VERSION 5.8 ;
BUSBITCHARS "[]" ;
DIVIDERCHAR "/" ;
UNITS
    DATABASE MICRONS 1000 ;
END UNITS

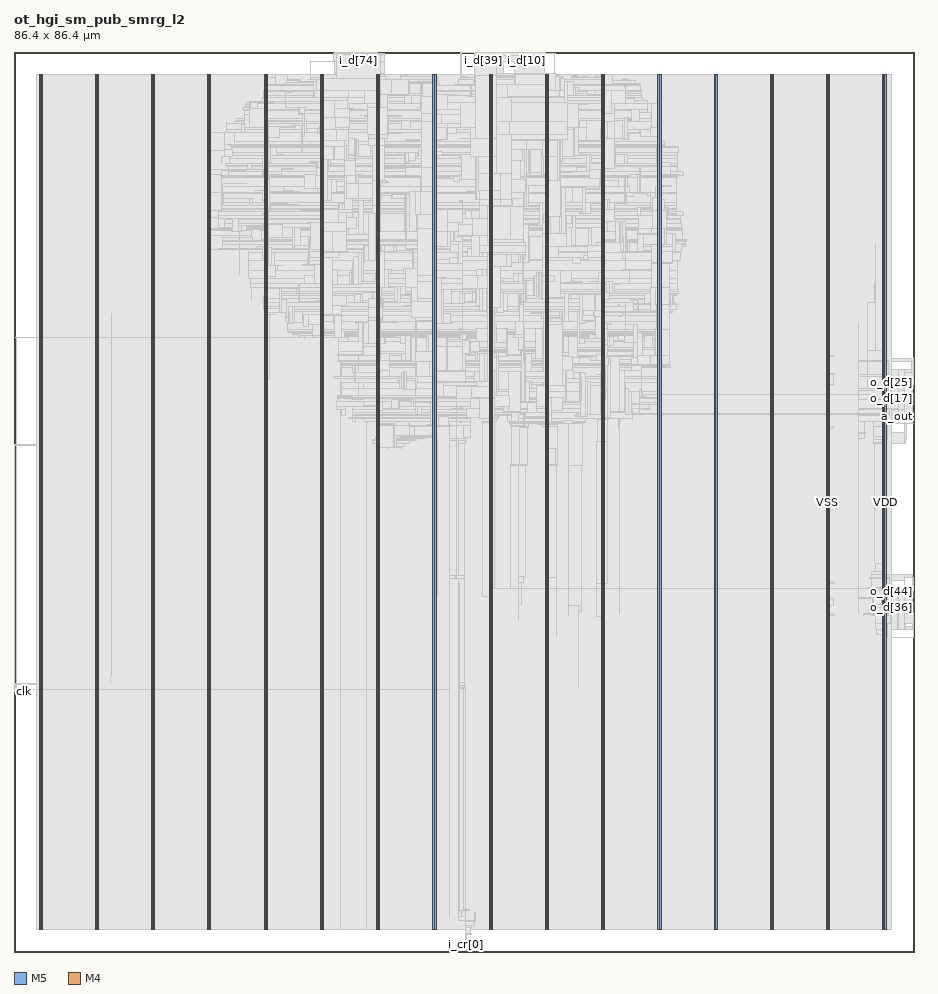
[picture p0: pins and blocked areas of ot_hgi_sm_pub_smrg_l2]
MACRO ot_hgi_sm_pub_smrg_l2
  FOREIGN ot_hgi_sm_pub_smrg_l2 0 0 ;
  CLASS BLOCK ;
  SIZE 86.4 BY 86.4 ;
  PIN a_in[0]
    DIRECTION INPUT ;
    USE SIGNAL ;
    PORT
      LAYER M5 ;
        RECT  48.048 86.316 48.072 86.4 ;
    END
  END a_in[0]
  PIN a_in[1]
    DIRECTION INPUT ;
    USE SIGNAL ;
    PORT
      LAYER M5 ;
        RECT  48.144 86.316 48.168 86.4 ;
    END
  END a_in[1]
  PIN a_out
    DIRECTION OUTPUT ;
    USE SIGNAL ;
    PORT
      LAYER M4 ;
        RECT  86.316 51.408 86.4 51.432 ;
    END
  END a_out
  PIN clk
    DIRECTION INPUT ;
    USE SIGNAL ;
    PORT
      LAYER M4 ;
        RECT  0 25.008 0.084 25.032 ;
    END
  END clk
  PIN i_cr[0]
    DIRECTION OUTPUT ;
    USE SIGNAL ;
    PORT
      LAYER M5 ;
        RECT  43.344 0 43.368 0.084 ;
    END
  END i_cr[0]
  PIN i_cr[1]
    DIRECTION OUTPUT ;
    USE SIGNAL ;
    PORT
      LAYER M5 ;
        RECT  43.44 0 43.464 0.084 ;
    END
  END i_cr[1]
  PIN i_d[0]
    DIRECTION INPUT ;
    USE SIGNAL ;
    PORT
      LAYER M5 ;
        RECT  48.24 86.316 48.264 86.4 ;
    END
  END i_d[0]
  PIN i_d[100]
    DIRECTION INPUT ;
    USE SIGNAL ;
    PORT
      LAYER M5 ;
        RECT  31.344 86.316 31.368 86.4 ;
    END
  END i_d[100]
  PIN i_d[101]
    DIRECTION INPUT ;
    USE SIGNAL ;
    PORT
      LAYER M5 ;
        RECT  31.44 86.316 31.464 86.4 ;
    END
  END i_d[101]
  PIN i_d[102]
    DIRECTION INPUT ;
    USE SIGNAL ;
    PORT
      LAYER M5 ;
        RECT  31.536 86.316 31.56 86.4 ;
    END
  END i_d[102]
  PIN i_d[103]
    DIRECTION INPUT ;
    USE SIGNAL ;
    PORT
      LAYER M5 ;
        RECT  31.632 86.316 31.656 86.4 ;
    END
  END i_d[103]
  PIN i_d[10]
    DIRECTION INPUT ;
    USE SIGNAL ;
    PORT
      LAYER M5 ;
        RECT  49.2 86.316 49.224 86.4 ;
    END
  END i_d[10]
  PIN i_d[11]
    DIRECTION INPUT ;
    USE SIGNAL ;
    PORT
      LAYER M5 ;
        RECT  49.296 86.316 49.32 86.4 ;
    END
  END i_d[11]
  PIN i_d[12]
    DIRECTION INPUT ;
    USE SIGNAL ;
    PORT
      LAYER M5 ;
        RECT  49.392 86.316 49.416 86.4 ;
    END
  END i_d[12]
  PIN i_d[13]
    DIRECTION INPUT ;
    USE SIGNAL ;
    PORT
      LAYER M5 ;
        RECT  49.488 86.316 49.512 86.4 ;
    END
  END i_d[13]
  PIN i_d[14]
    DIRECTION INPUT ;
    USE SIGNAL ;
    PORT
      LAYER M5 ;
        RECT  49.584 86.316 49.608 86.4 ;
    END
  END i_d[14]
  PIN i_d[15]
    DIRECTION INPUT ;
    USE SIGNAL ;
    PORT
      LAYER M5 ;
        RECT  49.68 86.316 49.704 86.4 ;
    END
  END i_d[15]
  PIN i_d[16]
    DIRECTION INPUT ;
    USE SIGNAL ;
    PORT
      LAYER M5 ;
        RECT  49.776 86.316 49.8 86.4 ;
    END
  END i_d[16]
  PIN i_d[17]
    DIRECTION INPUT ;
    USE SIGNAL ;
    PORT
      LAYER M5 ;
        RECT  49.872 86.316 49.896 86.4 ;
    END
  END i_d[17]
  PIN i_d[18]
    DIRECTION INPUT ;
    USE SIGNAL ;
    PORT
      LAYER M5 ;
        RECT  49.968 86.316 49.992 86.4 ;
    END
  END i_d[18]
  PIN i_d[19]
    DIRECTION INPUT ;
    USE SIGNAL ;
    PORT
      LAYER M5 ;
        RECT  50.064 86.316 50.088 86.4 ;
    END
  END i_d[19]
  PIN i_d[1]
    DIRECTION INPUT ;
    USE SIGNAL ;
    PORT
      LAYER M5 ;
        RECT  48.336 86.316 48.36 86.4 ;
    END
  END i_d[1]
  PIN i_d[20]
    DIRECTION INPUT ;
    USE SIGNAL ;
    PORT
      LAYER M5 ;
        RECT  50.16 86.316 50.184 86.4 ;
    END
  END i_d[20]
  PIN i_d[21]
    DIRECTION INPUT ;
    USE SIGNAL ;
    PORT
      LAYER M5 ;
        RECT  50.256 86.316 50.28 86.4 ;
    END
  END i_d[21]
  PIN i_d[22]
    DIRECTION INPUT ;
    USE SIGNAL ;
    PORT
      LAYER M5 ;
        RECT  50.352 86.316 50.376 86.4 ;
    END
  END i_d[22]
  PIN i_d[23]
    DIRECTION INPUT ;
    USE SIGNAL ;
    PORT
      LAYER M5 ;
        RECT  50.448 86.316 50.472 86.4 ;
    END
  END i_d[23]
  PIN i_d[24]
    DIRECTION INPUT ;
    USE SIGNAL ;
    PORT
      LAYER M5 ;
        RECT  50.544 86.316 50.568 86.4 ;
    END
  END i_d[24]
  PIN i_d[25]
    DIRECTION INPUT ;
    USE SIGNAL ;
    PORT
      LAYER M5 ;
        RECT  50.64 86.316 50.664 86.4 ;
    END
  END i_d[25]
  PIN i_d[26]
    DIRECTION INPUT ;
    USE SIGNAL ;
    PORT
      LAYER M5 ;
        RECT  50.736 86.316 50.76 86.4 ;
    END
  END i_d[26]
  PIN i_d[27]
    DIRECTION INPUT ;
    USE SIGNAL ;
    PORT
      LAYER M5 ;
        RECT  50.832 86.316 50.856 86.4 ;
    END
  END i_d[27]
  PIN i_d[28]
    DIRECTION INPUT ;
    USE SIGNAL ;
    PORT
      LAYER M5 ;
        RECT  50.928 86.316 50.952 86.4 ;
    END
  END i_d[28]
  PIN i_d[29]
    DIRECTION INPUT ;
    USE SIGNAL ;
    PORT
      LAYER M5 ;
        RECT  51.024 86.316 51.048 86.4 ;
    END
  END i_d[29]
  PIN i_d[2]
    DIRECTION INPUT ;
    USE SIGNAL ;
    PORT
      LAYER M5 ;
        RECT  48.432 86.316 48.456 86.4 ;
    END
  END i_d[2]
  PIN i_d[30]
    DIRECTION INPUT ;
    USE SIGNAL ;
    PORT
      LAYER M5 ;
        RECT  44.208 86.316 44.232 86.4 ;
    END
  END i_d[30]
  PIN i_d[31]
    DIRECTION INPUT ;
    USE SIGNAL ;
    PORT
      LAYER M5 ;
        RECT  44.304 86.316 44.328 86.4 ;
    END
  END i_d[31]
  PIN i_d[32]
    DIRECTION INPUT ;
    USE SIGNAL ;
    PORT
      LAYER M5 ;
        RECT  44.4 86.316 44.424 86.4 ;
    END
  END i_d[32]
  PIN i_d[33]
    DIRECTION INPUT ;
    USE SIGNAL ;
    PORT
      LAYER M5 ;
        RECT  44.496 86.316 44.52 86.4 ;
    END
  END i_d[33]
  PIN i_d[34]
    DIRECTION INPUT ;
    USE SIGNAL ;
    PORT
      LAYER M5 ;
        RECT  44.592 86.316 44.616 86.4 ;
    END
  END i_d[34]
  PIN i_d[35]
    DIRECTION INPUT ;
    USE SIGNAL ;
    PORT
      LAYER M5 ;
        RECT  44.688 86.316 44.712 86.4 ;
    END
  END i_d[35]
  PIN i_d[36]
    DIRECTION INPUT ;
    USE SIGNAL ;
    PORT
      LAYER M5 ;
        RECT  44.784 86.316 44.808 86.4 ;
    END
  END i_d[36]
  PIN i_d[37]
    DIRECTION INPUT ;
    USE SIGNAL ;
    PORT
      LAYER M5 ;
        RECT  44.88 86.316 44.904 86.4 ;
    END
  END i_d[37]
  PIN i_d[38]
    DIRECTION INPUT ;
    USE SIGNAL ;
    PORT
      LAYER M5 ;
        RECT  44.976 86.316 45 86.4 ;
    END
  END i_d[38]
  PIN i_d[39]
    DIRECTION INPUT ;
    USE SIGNAL ;
    PORT
      LAYER M5 ;
        RECT  45.072 86.316 45.096 86.4 ;
    END
  END i_d[39]
  PIN i_d[3]
    DIRECTION INPUT ;
    USE SIGNAL ;
    PORT
      LAYER M5 ;
        RECT  48.528 86.316 48.552 86.4 ;
    END
  END i_d[3]
  PIN i_d[40]
    DIRECTION INPUT ;
    USE SIGNAL ;
    PORT
      LAYER M5 ;
        RECT  45.168 86.316 45.192 86.4 ;
    END
  END i_d[40]
  PIN i_d[41]
    DIRECTION INPUT ;
    USE SIGNAL ;
    PORT
      LAYER M5 ;
        RECT  45.264 86.316 45.288 86.4 ;
    END
  END i_d[41]
  PIN i_d[42]
    DIRECTION INPUT ;
    USE SIGNAL ;
    PORT
      LAYER M5 ;
        RECT  45.36 86.316 45.384 86.4 ;
    END
  END i_d[42]
  PIN i_d[43]
    DIRECTION INPUT ;
    USE SIGNAL ;
    PORT
      LAYER M5 ;
        RECT  45.456 86.316 45.48 86.4 ;
    END
  END i_d[43]
  PIN i_d[44]
    DIRECTION INPUT ;
    USE SIGNAL ;
    PORT
      LAYER M5 ;
        RECT  45.552 86.316 45.576 86.4 ;
    END
  END i_d[44]
  PIN i_d[45]
    DIRECTION INPUT ;
    USE SIGNAL ;
    PORT
      LAYER M5 ;
        RECT  45.648 86.316 45.672 86.4 ;
    END
  END i_d[45]
  PIN i_d[46]
    DIRECTION INPUT ;
    USE SIGNAL ;
    PORT
      LAYER M5 ;
        RECT  45.744 86.316 45.768 86.4 ;
    END
  END i_d[46]
  PIN i_d[47]
    DIRECTION INPUT ;
    USE SIGNAL ;
    PORT
      LAYER M5 ;
        RECT  45.84 86.316 45.864 86.4 ;
    END
  END i_d[47]
  PIN i_d[48]
    DIRECTION INPUT ;
    USE SIGNAL ;
    PORT
      LAYER M5 ;
        RECT  45.936 86.316 45.96 86.4 ;
    END
  END i_d[48]
  PIN i_d[49]
    DIRECTION INPUT ;
    USE SIGNAL ;
    PORT
      LAYER M5 ;
        RECT  46.032 86.316 46.056 86.4 ;
    END
  END i_d[49]
  PIN i_d[4]
    DIRECTION INPUT ;
    USE SIGNAL ;
    PORT
      LAYER M5 ;
        RECT  48.624 86.316 48.648 86.4 ;
    END
  END i_d[4]
  PIN i_d[50]
    DIRECTION INPUT ;
    USE SIGNAL ;
    PORT
      LAYER M5 ;
        RECT  46.128 86.316 46.152 86.4 ;
    END
  END i_d[50]
  PIN i_d[51]
    DIRECTION INPUT ;
    USE SIGNAL ;
    PORT
      LAYER M5 ;
        RECT  46.224 86.316 46.248 86.4 ;
    END
  END i_d[51]
  PIN i_d[52]
    DIRECTION INPUT ;
    USE SIGNAL ;
    PORT
      LAYER M5 ;
        RECT  46.32 86.316 46.344 86.4 ;
    END
  END i_d[52]
  PIN i_d[53]
    DIRECTION INPUT ;
    USE SIGNAL ;
    PORT
      LAYER M5 ;
        RECT  46.416 86.316 46.44 86.4 ;
    END
  END i_d[53]
  PIN i_d[54]
    DIRECTION INPUT ;
    USE SIGNAL ;
    PORT
      LAYER M5 ;
        RECT  46.512 86.316 46.536 86.4 ;
    END
  END i_d[54]
  PIN i_d[55]
    DIRECTION INPUT ;
    USE SIGNAL ;
    PORT
      LAYER M5 ;
        RECT  46.608 86.316 46.632 86.4 ;
    END
  END i_d[55]
  PIN i_d[56]
    DIRECTION INPUT ;
    USE SIGNAL ;
    PORT
      LAYER M5 ;
        RECT  46.704 86.316 46.728 86.4 ;
    END
  END i_d[56]
  PIN i_d[57]
    DIRECTION INPUT ;
    USE SIGNAL ;
    PORT
      LAYER M5 ;
        RECT  46.8 86.316 46.824 86.4 ;
    END
  END i_d[57]
  PIN i_d[58]
    DIRECTION INPUT ;
    USE SIGNAL ;
    PORT
      LAYER M5 ;
        RECT  46.896 86.316 46.92 86.4 ;
    END
  END i_d[58]
  PIN i_d[59]
    DIRECTION INPUT ;
    USE SIGNAL ;
    PORT
      LAYER M5 ;
        RECT  46.992 86.316 47.016 86.4 ;
    END
  END i_d[59]
  PIN i_d[5]
    DIRECTION INPUT ;
    USE SIGNAL ;
    PORT
      LAYER M5 ;
        RECT  48.72 86.316 48.744 86.4 ;
    END
  END i_d[5]
  PIN i_d[60]
    DIRECTION INPUT ;
    USE SIGNAL ;
    PORT
      LAYER M5 ;
        RECT  47.088 86.316 47.112 86.4 ;
    END
  END i_d[60]
  PIN i_d[61]
    DIRECTION INPUT ;
    USE SIGNAL ;
    PORT
      LAYER M5 ;
        RECT  47.184 86.316 47.208 86.4 ;
    END
  END i_d[61]
  PIN i_d[62]
    DIRECTION INPUT ;
    USE SIGNAL ;
    PORT
      LAYER M5 ;
        RECT  31.92 86.316 31.944 86.4 ;
    END
  END i_d[62]
  PIN i_d[63]
    DIRECTION INPUT ;
    USE SIGNAL ;
    PORT
      LAYER M5 ;
        RECT  32.016 86.316 32.04 86.4 ;
    END
  END i_d[63]
  PIN i_d[64]
    DIRECTION INPUT ;
    USE SIGNAL ;
    PORT
      LAYER M5 ;
        RECT  32.112 86.316 32.136 86.4 ;
    END
  END i_d[64]
  PIN i_d[65]
    DIRECTION INPUT ;
    USE SIGNAL ;
    PORT
      LAYER M5 ;
        RECT  32.208 86.316 32.232 86.4 ;
    END
  END i_d[65]
  PIN i_d[66]
    DIRECTION INPUT ;
    USE SIGNAL ;
    PORT
      LAYER M5 ;
        RECT  32.304 86.316 32.328 86.4 ;
    END
  END i_d[66]
  PIN i_d[67]
    DIRECTION INPUT ;
    USE SIGNAL ;
    PORT
      LAYER M5 ;
        RECT  32.4 86.316 32.424 86.4 ;
    END
  END i_d[67]
  PIN i_d[68]
    DIRECTION INPUT ;
    USE SIGNAL ;
    PORT
      LAYER M5 ;
        RECT  32.496 86.316 32.52 86.4 ;
    END
  END i_d[68]
  PIN i_d[69]
    DIRECTION INPUT ;
    USE SIGNAL ;
    PORT
      LAYER M5 ;
        RECT  32.592 86.316 32.616 86.4 ;
    END
  END i_d[69]
  PIN i_d[6]
    DIRECTION INPUT ;
    USE SIGNAL ;
    PORT
      LAYER M5 ;
        RECT  48.816 86.316 48.84 86.4 ;
    END
  END i_d[6]
  PIN i_d[70]
    DIRECTION INPUT ;
    USE SIGNAL ;
    PORT
      LAYER M5 ;
        RECT  32.688 86.316 32.712 86.4 ;
    END
  END i_d[70]
  PIN i_d[71]
    DIRECTION INPUT ;
    USE SIGNAL ;
    PORT
      LAYER M5 ;
        RECT  32.784 86.316 32.808 86.4 ;
    END
  END i_d[71]
  PIN i_d[72]
    DIRECTION INPUT ;
    USE SIGNAL ;
    PORT
      LAYER M5 ;
        RECT  32.88 86.316 32.904 86.4 ;
    END
  END i_d[72]
  PIN i_d[73]
    DIRECTION INPUT ;
    USE SIGNAL ;
    PORT
      LAYER M5 ;
        RECT  32.976 86.316 33 86.4 ;
    END
  END i_d[73]
  PIN i_d[74]
    DIRECTION INPUT ;
    USE SIGNAL ;
    PORT
      LAYER M5 ;
        RECT  33.072 86.316 33.096 86.4 ;
    END
  END i_d[74]
  PIN i_d[75]
    DIRECTION INPUT ;
    USE SIGNAL ;
    PORT
      LAYER M5 ;
        RECT  33.168 86.316 33.192 86.4 ;
    END
  END i_d[75]
  PIN i_d[76]
    DIRECTION INPUT ;
    USE SIGNAL ;
    PORT
      LAYER M5 ;
        RECT  33.264 86.316 33.288 86.4 ;
    END
  END i_d[76]
  PIN i_d[77]
    DIRECTION INPUT ;
    USE SIGNAL ;
    PORT
      LAYER M5 ;
        RECT  33.36 86.316 33.384 86.4 ;
    END
  END i_d[77]
  PIN i_d[78]
    DIRECTION INPUT ;
    USE SIGNAL ;
    PORT
      LAYER M5 ;
        RECT  33.456 86.316 33.48 86.4 ;
    END
  END i_d[78]
  PIN i_d[79]
    DIRECTION INPUT ;
    USE SIGNAL ;
    PORT
      LAYER M5 ;
        RECT  33.552 86.316 33.576 86.4 ;
    END
  END i_d[79]
  PIN i_d[7]
    DIRECTION INPUT ;
    USE SIGNAL ;
    PORT
      LAYER M5 ;
        RECT  48.912 86.316 48.936 86.4 ;
    END
  END i_d[7]
  PIN i_d[80]
    DIRECTION INPUT ;
    USE SIGNAL ;
    PORT
      LAYER M5 ;
        RECT  33.648 86.316 33.672 86.4 ;
    END
  END i_d[80]
  PIN i_d[81]
    DIRECTION INPUT ;
    USE SIGNAL ;
    PORT
      LAYER M5 ;
        RECT  33.744 86.316 33.768 86.4 ;
    END
  END i_d[81]
  PIN i_d[82]
    DIRECTION INPUT ;
    USE SIGNAL ;
    PORT
      LAYER M5 ;
        RECT  33.84 86.316 33.864 86.4 ;
    END
  END i_d[82]
  PIN i_d[83]
    DIRECTION INPUT ;
    USE SIGNAL ;
    PORT
      LAYER M5 ;
        RECT  33.936 86.316 33.96 86.4 ;
    END
  END i_d[83]
  PIN i_d[84]
    DIRECTION INPUT ;
    USE SIGNAL ;
    PORT
      LAYER M5 ;
        RECT  34.032 86.316 34.056 86.4 ;
    END
  END i_d[84]
  PIN i_d[85]
    DIRECTION INPUT ;
    USE SIGNAL ;
    PORT
      LAYER M5 ;
        RECT  34.128 86.316 34.152 86.4 ;
    END
  END i_d[85]
  PIN i_d[86]
    DIRECTION INPUT ;
    USE SIGNAL ;
    PORT
      LAYER M5 ;
        RECT  34.224 86.316 34.248 86.4 ;
    END
  END i_d[86]
  PIN i_d[87]
    DIRECTION INPUT ;
    USE SIGNAL ;
    PORT
      LAYER M5 ;
        RECT  34.32 86.316 34.344 86.4 ;
    END
  END i_d[87]
  PIN i_d[88]
    DIRECTION INPUT ;
    USE SIGNAL ;
    PORT
      LAYER M5 ;
        RECT  34.416 86.316 34.44 86.4 ;
    END
  END i_d[88]
  PIN i_d[89]
    DIRECTION INPUT ;
    USE SIGNAL ;
    PORT
      LAYER M5 ;
        RECT  34.512 86.316 34.536 86.4 ;
    END
  END i_d[89]
  PIN i_d[8]
    DIRECTION INPUT ;
    USE SIGNAL ;
    PORT
      LAYER M5 ;
        RECT  49.008 86.316 49.032 86.4 ;
    END
  END i_d[8]
  PIN i_d[90]
    DIRECTION INPUT ;
    USE SIGNAL ;
    PORT
      LAYER M5 ;
        RECT  34.608 86.316 34.632 86.4 ;
    END
  END i_d[90]
  PIN i_d[91]
    DIRECTION INPUT ;
    USE SIGNAL ;
    PORT
      LAYER M5 ;
        RECT  34.704 86.316 34.728 86.4 ;
    END
  END i_d[91]
  PIN i_d[92]
    DIRECTION INPUT ;
    USE SIGNAL ;
    PORT
      LAYER M5 ;
        RECT  34.8 86.316 34.824 86.4 ;
    END
  END i_d[92]
  PIN i_d[93]
    DIRECTION INPUT ;
    USE SIGNAL ;
    PORT
      LAYER M5 ;
        RECT  34.896 86.316 34.92 86.4 ;
    END
  END i_d[93]
  PIN i_d[94]
    DIRECTION INPUT ;
    USE SIGNAL ;
    PORT
      LAYER M5 ;
        RECT  30.768 86.316 30.792 86.4 ;
    END
  END i_d[94]
  PIN i_d[95]
    DIRECTION INPUT ;
    USE SIGNAL ;
    PORT
      LAYER M5 ;
        RECT  30.864 86.316 30.888 86.4 ;
    END
  END i_d[95]
  PIN i_d[96]
    DIRECTION INPUT ;
    USE SIGNAL ;
    PORT
      LAYER M5 ;
        RECT  30.96 86.316 30.984 86.4 ;
    END
  END i_d[96]
  PIN i_d[97]
    DIRECTION INPUT ;
    USE SIGNAL ;
    PORT
      LAYER M5 ;
        RECT  31.056 86.316 31.08 86.4 ;
    END
  END i_d[97]
  PIN i_d[98]
    DIRECTION INPUT ;
    USE SIGNAL ;
    PORT
      LAYER M5 ;
        RECT  31.152 86.316 31.176 86.4 ;
    END
  END i_d[98]
  PIN i_d[99]
    DIRECTION INPUT ;
    USE SIGNAL ;
    PORT
      LAYER M5 ;
        RECT  31.248 86.316 31.272 86.4 ;
    END
  END i_d[99]
  PIN i_d[9]
    DIRECTION INPUT ;
    USE SIGNAL ;
    PORT
      LAYER M5 ;
        RECT  49.104 86.316 49.128 86.4 ;
    END
  END i_d[9]
  PIN i_v[0]
    DIRECTION INPUT ;
    USE SIGNAL ;
    PORT
      LAYER M5 ;
        RECT  31.728 86.316 31.752 86.4 ;
    END
  END i_v[0]
  PIN i_v[1]
    DIRECTION INPUT ;
    USE SIGNAL ;
    PORT
      LAYER M5 ;
        RECT  31.824 86.316 31.848 86.4 ;
    END
  END i_v[1]
  PIN o_cr
    DIRECTION INPUT ;
    USE SIGNAL ;
    PORT
      LAYER M4 ;
        RECT  0 25.104 0.084 25.128 ;
    END
  END o_cr
  PIN o_d[0]
    DIRECTION OUTPUT ;
    USE SIGNAL ;
    PORT
      LAYER M4 ;
        RECT  86.316 51.504 86.4 51.528 ;
    END
  END o_d[0]
  PIN o_d[10]
    DIRECTION OUTPUT ;
    USE SIGNAL ;
    PORT
      LAYER M4 ;
        RECT  86.316 52.464 86.4 52.488 ;
    END
  END o_d[10]
  PIN o_d[11]
    DIRECTION OUTPUT ;
    USE SIGNAL ;
    PORT
      LAYER M4 ;
        RECT  86.316 52.56 86.4 52.584 ;
    END
  END o_d[11]
  PIN o_d[12]
    DIRECTION OUTPUT ;
    USE SIGNAL ;
    PORT
      LAYER M4 ;
        RECT  86.316 52.656 86.4 52.68 ;
    END
  END o_d[12]
  PIN o_d[13]
    DIRECTION OUTPUT ;
    USE SIGNAL ;
    PORT
      LAYER M4 ;
        RECT  86.316 52.752 86.4 52.776 ;
    END
  END o_d[13]
  PIN o_d[14]
    DIRECTION OUTPUT ;
    USE SIGNAL ;
    PORT
      LAYER M4 ;
        RECT  86.316 52.848 86.4 52.872 ;
    END
  END o_d[14]
  PIN o_d[15]
    DIRECTION OUTPUT ;
    USE SIGNAL ;
    PORT
      LAYER M4 ;
        RECT  86.316 52.944 86.4 52.968 ;
    END
  END o_d[15]
  PIN o_d[16]
    DIRECTION OUTPUT ;
    USE SIGNAL ;
    PORT
      LAYER M4 ;
        RECT  86.316 53.04 86.4 53.064 ;
    END
  END o_d[16]
  PIN o_d[17]
    DIRECTION OUTPUT ;
    USE SIGNAL ;
    PORT
      LAYER M4 ;
        RECT  86.316 53.136 86.4 53.16 ;
    END
  END o_d[17]
  PIN o_d[18]
    DIRECTION OUTPUT ;
    USE SIGNAL ;
    PORT
      LAYER M4 ;
        RECT  86.316 53.232 86.4 53.256 ;
    END
  END o_d[18]
  PIN o_d[19]
    DIRECTION OUTPUT ;
    USE SIGNAL ;
    PORT
      LAYER M4 ;
        RECT  86.316 53.328 86.4 53.352 ;
    END
  END o_d[19]
  PIN o_d[1]
    DIRECTION OUTPUT ;
    USE SIGNAL ;
    PORT
      LAYER M4 ;
        RECT  86.316 51.6 86.4 51.624 ;
    END
  END o_d[1]
  PIN o_d[20]
    DIRECTION OUTPUT ;
    USE SIGNAL ;
    PORT
      LAYER M4 ;
        RECT  86.316 53.424 86.4 53.448 ;
    END
  END o_d[20]
  PIN o_d[21]
    DIRECTION OUTPUT ;
    USE SIGNAL ;
    PORT
      LAYER M4 ;
        RECT  86.316 53.52 86.4 53.544 ;
    END
  END o_d[21]
  PIN o_d[22]
    DIRECTION OUTPUT ;
    USE SIGNAL ;
    PORT
      LAYER M4 ;
        RECT  86.316 53.616 86.4 53.64 ;
    END
  END o_d[22]
  PIN o_d[23]
    DIRECTION OUTPUT ;
    USE SIGNAL ;
    PORT
      LAYER M4 ;
        RECT  86.316 53.712 86.4 53.736 ;
    END
  END o_d[23]
  PIN o_d[24]
    DIRECTION OUTPUT ;
    USE SIGNAL ;
    PORT
      LAYER M4 ;
        RECT  86.316 53.808 86.4 53.832 ;
    END
  END o_d[24]
  PIN o_d[25]
    DIRECTION OUTPUT ;
    USE SIGNAL ;
    PORT
      LAYER M4 ;
        RECT  86.316 53.904 86.4 53.928 ;
    END
  END o_d[25]
  PIN o_d[26]
    DIRECTION OUTPUT ;
    USE SIGNAL ;
    PORT
      LAYER M4 ;
        RECT  86.316 54 86.4 54.024 ;
    END
  END o_d[26]
  PIN o_d[27]
    DIRECTION OUTPUT ;
    USE SIGNAL ;
    PORT
      LAYER M4 ;
        RECT  86.316 54.096 86.4 54.12 ;
    END
  END o_d[27]
  PIN o_d[28]
    DIRECTION OUTPUT ;
    USE SIGNAL ;
    PORT
      LAYER M4 ;
        RECT  86.316 54.192 86.4 54.216 ;
    END
  END o_d[28]
  PIN o_d[29]
    DIRECTION OUTPUT ;
    USE SIGNAL ;
    PORT
      LAYER M4 ;
        RECT  86.316 54.288 86.4 54.312 ;
    END
  END o_d[29]
  PIN o_d[2]
    DIRECTION OUTPUT ;
    USE SIGNAL ;
    PORT
      LAYER M4 ;
        RECT  86.316 51.696 86.4 51.72 ;
    END
  END o_d[2]
  PIN o_d[30]
    DIRECTION OUTPUT ;
    USE SIGNAL ;
    PORT
      LAYER M4 ;
        RECT  86.316 54.384 86.4 54.408 ;
    END
  END o_d[30]
  PIN o_d[31]
    DIRECTION OUTPUT ;
    USE SIGNAL ;
    PORT
      LAYER M4 ;
        RECT  86.316 32.592 86.4 32.616 ;
    END
  END o_d[31]
  PIN o_d[32]
    DIRECTION OUTPUT ;
    USE SIGNAL ;
    PORT
      LAYER M4 ;
        RECT  86.316 32.688 86.4 32.712 ;
    END
  END o_d[32]
  PIN o_d[33]
    DIRECTION OUTPUT ;
    USE SIGNAL ;
    PORT
      LAYER M4 ;
        RECT  86.316 32.784 86.4 32.808 ;
    END
  END o_d[33]
  PIN o_d[34]
    DIRECTION OUTPUT ;
    USE SIGNAL ;
    PORT
      LAYER M4 ;
        RECT  86.316 32.88 86.4 32.904 ;
    END
  END o_d[34]
  PIN o_d[35]
    DIRECTION OUTPUT ;
    USE SIGNAL ;
    PORT
      LAYER M4 ;
        RECT  86.316 32.976 86.4 33 ;
    END
  END o_d[35]
  PIN o_d[36]
    DIRECTION OUTPUT ;
    USE SIGNAL ;
    PORT
      LAYER M4 ;
        RECT  86.316 33.072 86.4 33.096 ;
    END
  END o_d[36]
  PIN o_d[37]
    DIRECTION OUTPUT ;
    USE SIGNAL ;
    PORT
      LAYER M4 ;
        RECT  86.316 33.168 86.4 33.192 ;
    END
  END o_d[37]
  PIN o_d[38]
    DIRECTION OUTPUT ;
    USE SIGNAL ;
    PORT
      LAYER M4 ;
        RECT  86.316 33.264 86.4 33.288 ;
    END
  END o_d[38]
  PIN o_d[39]
    DIRECTION OUTPUT ;
    USE SIGNAL ;
    PORT
      LAYER M4 ;
        RECT  86.316 33.36 86.4 33.384 ;
    END
  END o_d[39]
  PIN o_d[3]
    DIRECTION OUTPUT ;
    USE SIGNAL ;
    PORT
      LAYER M4 ;
        RECT  86.316 51.792 86.4 51.816 ;
    END
  END o_d[3]
  PIN o_d[40]
    DIRECTION OUTPUT ;
    USE SIGNAL ;
    PORT
      LAYER M4 ;
        RECT  86.316 33.456 86.4 33.48 ;
    END
  END o_d[40]
  PIN o_d[41]
    DIRECTION OUTPUT ;
    USE SIGNAL ;
    PORT
      LAYER M4 ;
        RECT  86.316 33.552 86.4 33.576 ;
    END
  END o_d[41]
  PIN o_d[42]
    DIRECTION OUTPUT ;
    USE SIGNAL ;
    PORT
      LAYER M4 ;
        RECT  86.316 33.648 86.4 33.672 ;
    END
  END o_d[42]
  PIN o_d[43]
    DIRECTION OUTPUT ;
    USE SIGNAL ;
    PORT
      LAYER M4 ;
        RECT  86.316 33.744 86.4 33.768 ;
    END
  END o_d[43]
  PIN o_d[44]
    DIRECTION OUTPUT ;
    USE SIGNAL ;
    PORT
      LAYER M4 ;
        RECT  86.316 33.84 86.4 33.864 ;
    END
  END o_d[44]
  PIN o_d[45]
    DIRECTION OUTPUT ;
    USE SIGNAL ;
    PORT
      LAYER M4 ;
        RECT  86.316 33.936 86.4 33.96 ;
    END
  END o_d[45]
  PIN o_d[46]
    DIRECTION OUTPUT ;
    USE SIGNAL ;
    PORT
      LAYER M4 ;
        RECT  86.316 34.032 86.4 34.056 ;
    END
  END o_d[46]
  PIN o_d[47]
    DIRECTION OUTPUT ;
    USE SIGNAL ;
    PORT
      LAYER M4 ;
        RECT  86.316 34.128 86.4 34.152 ;
    END
  END o_d[47]
  PIN o_d[48]
    DIRECTION OUTPUT ;
    USE SIGNAL ;
    PORT
      LAYER M4 ;
        RECT  86.316 34.224 86.4 34.248 ;
    END
  END o_d[48]
  PIN o_d[49]
    DIRECTION OUTPUT ;
    USE SIGNAL ;
    PORT
      LAYER M4 ;
        RECT  86.316 34.32 86.4 34.344 ;
    END
  END o_d[49]
  PIN o_d[4]
    DIRECTION OUTPUT ;
    USE SIGNAL ;
    PORT
      LAYER M4 ;
        RECT  86.316 51.888 86.4 51.912 ;
    END
  END o_d[4]
  PIN o_d[50]
    DIRECTION OUTPUT ;
    USE SIGNAL ;
    PORT
      LAYER M4 ;
        RECT  86.316 34.416 86.4 34.44 ;
    END
  END o_d[50]
  PIN o_d[51]
    DIRECTION OUTPUT ;
    USE SIGNAL ;
    PORT
      LAYER M4 ;
        RECT  86.316 34.512 86.4 34.536 ;
    END
  END o_d[51]
  PIN o_d[5]
    DIRECTION OUTPUT ;
    USE SIGNAL ;
    PORT
      LAYER M4 ;
        RECT  86.316 51.984 86.4 52.008 ;
    END
  END o_d[5]
  PIN o_d[6]
    DIRECTION OUTPUT ;
    USE SIGNAL ;
    PORT
      LAYER M4 ;
        RECT  86.316 52.08 86.4 52.104 ;
    END
  END o_d[6]
  PIN o_d[7]
    DIRECTION OUTPUT ;
    USE SIGNAL ;
    PORT
      LAYER M4 ;
        RECT  86.316 52.176 86.4 52.2 ;
    END
  END o_d[7]
  PIN o_d[8]
    DIRECTION OUTPUT ;
    USE SIGNAL ;
    PORT
      LAYER M4 ;
        RECT  86.316 52.272 86.4 52.296 ;
    END
  END o_d[8]
  PIN o_d[9]
    DIRECTION OUTPUT ;
    USE SIGNAL ;
    PORT
      LAYER M4 ;
        RECT  86.316 52.368 86.4 52.392 ;
    END
  END o_d[9]
  PIN o_v
    DIRECTION OUTPUT ;
    USE SIGNAL ;
    PORT
      LAYER M4 ;
        RECT  86.316 34.608 86.4 34.632 ;
    END
  END o_v
  PIN rn
    DIRECTION INPUT ;
    USE SIGNAL ;
    PORT
      LAYER M4 ;
        RECT  0 25.2 0.084 25.224 ;
    END
  END rn
  PIN xb
    DIRECTION INPUT ;
    USE SIGNAL ;
    PORT
      LAYER M4 ;
        RECT  0 25.296 0.084 25.32 ;
    END
  END xb
  PIN VDD
    DIRECTION INOUT ;
    USE POWER ;
    PORT
      LAYER M5 ;
        RECT  83.592 2.151 83.712 84.249 ;
        RECT  78.192 2.151 78.312 84.249 ;
        RECT  72.792 2.151 72.912 84.249 ;
        RECT  67.392 2.151 67.512 84.249 ;
        RECT  61.992 2.151 62.112 84.249 ;
        RECT  56.592 2.151 56.712 84.249 ;
        RECT  51.192 2.151 51.312 84.249 ;
        RECT  45.792 2.151 45.912 84.249 ;
        RECT  40.392 2.151 40.512 84.249 ;
        RECT  34.992 2.151 35.112 84.249 ;
        RECT  29.592 2.151 29.712 84.249 ;
        RECT  24.192 2.151 24.312 84.249 ;
        RECT  18.792 2.151 18.912 84.249 ;
        RECT  13.392 2.151 13.512 84.249 ;
        RECT  7.992 2.151 8.112 84.249 ;
        RECT  2.592 2.151 2.712 84.249 ;
    END
  END VDD
  PIN VSS
    DIRECTION INOUT ;
    USE GROUND ;
    PORT
      LAYER M5 ;
        RECT  83.4 2.137 83.52 84.263 ;
        RECT  78 2.137 78.12 84.263 ;
        RECT  72.6 2.137 72.72 84.263 ;
        RECT  67.2 2.137 67.32 84.263 ;
        RECT  61.8 2.137 61.92 84.263 ;
        RECT  56.4 2.137 56.52 84.263 ;
        RECT  51 2.137 51.12 84.263 ;
        RECT  45.6 2.137 45.72 84.263 ;
        RECT  40.2 2.137 40.32 84.263 ;
        RECT  34.8 2.137 34.92 84.263 ;
        RECT  29.4 2.137 29.52 84.263 ;
        RECT  24 2.137 24.12 84.263 ;
        RECT  18.6 2.137 18.72 84.263 ;
        RECT  13.2 2.137 13.32 84.263 ;
        RECT  7.8 2.137 7.92 84.263 ;
        RECT  2.4 2.137 2.52 84.263 ;
    END
  END VSS
  # OT_OBS_CLOSED layer=M5 d_um=1.536 added=113
  OBS
    LAYER RVTN ;
     RECT  2.16 2.16 84.24 2.295 ;
     RECT  2.16 2.565 84.24 2.835 ;
     RECT  2.16 3.105 84.24 3.375 ;
     RECT  2.16 3.645 84.24 3.915 ;
     RECT  2.16 4.185 84.24 4.455 ;
     RECT  2.16 4.725 84.24 4.995 ;
     RECT  2.16 5.265 84.24 5.535 ;
     RECT  2.16 5.805 84.24 6.075 ;
     RECT  2.16 6.345 84.24 6.615 ;
     RECT  2.16 6.885 84.24 7.155 ;
     RECT  2.16 7.425 84.24 7.695 ;
     RECT  2.16 7.965 84.24 8.235 ;
     RECT  2.16 8.505 84.24 8.775 ;
     RECT  2.16 9.045 84.24 9.315 ;
     RECT  2.16 9.585 84.24 9.855 ;
     RECT  2.16 10.125 84.24 10.395 ;
     RECT  2.16 10.665 84.24 10.935 ;
     RECT  2.16 11.205 84.24 11.475 ;
     RECT  2.16 11.745 84.24 12.015 ;
     RECT  2.16 12.285 84.24 12.555 ;
     RECT  2.16 12.825 84.24 13.095 ;
     RECT  2.16 13.365 84.24 13.635 ;
     RECT  2.16 13.905 84.24 14.175 ;
     RECT  2.16 14.445 84.24 14.715 ;
     RECT  2.16 14.985 84.24 15.255 ;
     RECT  2.16 15.525 84.24 15.795 ;
     RECT  2.16 16.065 84.24 16.335 ;
     RECT  2.16 16.605 84.24 16.875 ;
     RECT  2.16 17.145 84.24 17.415 ;
     RECT  2.16 17.685 84.24 17.955 ;
     RECT  2.16 18.225 84.24 18.495 ;
     RECT  2.16 18.765 84.24 19.035 ;
     RECT  2.16 19.305 84.24 19.575 ;
     RECT  2.16 19.845 84.24 20.115 ;
     RECT  2.16 20.385 84.24 20.655 ;
     RECT  2.16 20.925 84.24 21.195 ;
     RECT  2.16 21.465 84.24 21.735 ;
     RECT  2.16 22.005 84.24 22.275 ;
     RECT  2.16 22.545 84.24 22.815 ;
     RECT  2.16 23.085 84.24 23.355 ;
     RECT  2.16 23.625 84.24 23.895 ;
     RECT  2.16 24.165 84.24 24.435 ;
     RECT  2.16 24.705 84.24 24.975 ;
     RECT  2.16 25.245 84.24 25.515 ;
     RECT  2.16 25.785 84.24 26.055 ;
     RECT  2.16 26.325 84.24 26.595 ;
     RECT  2.16 26.865 84.24 27.135 ;
     RECT  2.16 27.405 84.24 27.675 ;
     RECT  2.16 27.945 84.24 28.215 ;
     RECT  2.16 28.485 84.24 28.755 ;
     RECT  2.16 29.025 84.24 29.295 ;
     RECT  2.16 29.565 84.24 29.835 ;
     RECT  2.16 30.105 84.24 30.375 ;
     RECT  2.16 30.645 84.24 30.915 ;
     RECT  2.16 31.185 84.24 31.455 ;
     RECT  2.16 31.725 84.24 31.995 ;
     RECT  2.16 32.265 84.24 32.535 ;
     RECT  2.16 32.805 84.24 33.075 ;
     RECT  2.16 33.345 84.24 33.615 ;
     RECT  2.16 33.885 84.24 34.155 ;
     RECT  2.16 34.425 84.24 34.695 ;
     RECT  2.16 34.965 84.24 35.235 ;
     RECT  2.16 35.505 84.24 35.775 ;
     RECT  2.16 36.045 84.24 36.315 ;
     RECT  2.16 36.585 84.24 36.855 ;
     RECT  2.16 37.125 84.24 37.395 ;
     RECT  2.16 37.665 84.24 37.935 ;
     RECT  2.16 38.205 84.24 38.475 ;
     RECT  2.16 38.745 84.24 39.015 ;
     RECT  2.16 39.285 84.24 39.555 ;
     RECT  2.16 39.825 84.24 40.095 ;
     RECT  2.16 40.365 84.24 40.635 ;
     RECT  2.16 40.905 84.24 41.175 ;
     RECT  2.16 41.445 84.24 41.715 ;
     RECT  2.16 41.985 84.24 42.255 ;
     RECT  2.16 42.525 84.24 42.795 ;
     RECT  2.16 43.065 84.24 43.335 ;
     RECT  2.16 43.605 84.24 43.875 ;
     RECT  2.16 44.145 84.24 44.415 ;
     RECT  2.16 44.685 84.24 44.955 ;
     RECT  2.16 45.225 84.24 45.495 ;
     RECT  2.16 45.765 84.24 46.035 ;
     RECT  2.16 46.305 84.24 46.575 ;
     RECT  2.16 46.845 84.24 47.115 ;
     RECT  2.16 47.385 84.24 47.655 ;
     RECT  2.16 47.925 84.24 48.195 ;
     RECT  2.16 48.465 84.24 48.735 ;
     RECT  2.16 49.005 84.24 49.275 ;
     RECT  2.16 49.545 84.24 49.815 ;
     RECT  2.16 50.085 84.24 50.355 ;
     RECT  2.16 50.625 84.24 50.895 ;
     RECT  2.16 51.165 84.24 51.435 ;
     RECT  2.16 51.705 84.24 51.975 ;
     RECT  2.16 52.245 84.24 52.515 ;
     RECT  2.16 52.785 84.24 53.055 ;
     RECT  2.16 53.325 84.24 53.595 ;
     RECT  2.16 53.865 84.24 54.135 ;
     RECT  2.16 54.405 84.24 54.675 ;
     RECT  2.16 54.945 84.24 55.215 ;
     RECT  2.16 55.485 84.24 55.755 ;
     RECT  2.16 56.025 84.24 56.295 ;
     RECT  2.16 56.565 84.24 56.835 ;
     RECT  2.16 57.105 84.24 57.375 ;
     RECT  2.16 57.645 84.24 57.915 ;
     RECT  2.16 58.185 84.24 58.455 ;
     RECT  2.16 58.725 84.24 58.995 ;
     RECT  2.16 59.265 84.24 59.535 ;
     RECT  2.16 59.805 84.24 60.075 ;
     RECT  2.16 60.345 84.24 60.615 ;
     RECT  2.16 60.885 84.24 61.155 ;
     RECT  2.16 61.425 84.24 61.695 ;
     RECT  2.16 61.965 84.24 62.235 ;
     RECT  2.16 62.505 84.24 62.775 ;
     RECT  2.16 63.045 84.24 63.315 ;
     RECT  2.16 63.585 84.24 63.855 ;
     RECT  2.16 64.125 84.24 64.395 ;
     RECT  2.16 64.665 84.24 64.935 ;
     RECT  2.16 65.205 84.24 65.475 ;
     RECT  2.16 65.745 84.24 66.015 ;
     RECT  2.16 66.285 84.24 66.555 ;
     RECT  2.16 66.825 84.24 67.095 ;
     RECT  2.16 67.365 84.24 67.635 ;
     RECT  2.16 67.905 84.24 68.175 ;
     RECT  2.16 68.445 84.24 68.715 ;
     RECT  2.16 68.985 84.24 69.255 ;
     RECT  2.16 69.525 84.24 69.795 ;
     RECT  2.16 70.065 84.24 70.335 ;
     RECT  2.16 70.605 84.24 70.875 ;
     RECT  2.16 71.145 84.24 71.415 ;
     RECT  2.16 71.685 84.24 71.955 ;
     RECT  2.16 72.225 84.24 72.495 ;
     RECT  2.16 72.765 84.24 73.035 ;
     RECT  2.16 73.305 84.24 73.575 ;
     RECT  2.16 73.845 84.24 74.115 ;
     RECT  2.16 74.385 84.24 74.655 ;
     RECT  2.16 74.925 84.24 75.195 ;
     RECT  2.16 75.465 84.24 75.735 ;
     RECT  2.16 76.005 84.24 76.275 ;
     RECT  2.16 76.545 84.24 76.815 ;
     RECT  2.16 77.085 84.24 77.355 ;
     RECT  2.16 77.625 84.24 77.895 ;
     RECT  2.16 78.165 84.24 78.435 ;
     RECT  2.16 78.705 84.24 78.975 ;
     RECT  2.16 79.245 84.24 79.515 ;
     RECT  2.16 79.785 84.24 80.055 ;
     RECT  2.16 80.325 84.24 80.595 ;
     RECT  2.16 80.865 84.24 81.135 ;
     RECT  2.16 81.405 84.24 81.675 ;
     RECT  2.16 81.945 84.24 82.215 ;
     RECT  2.16 82.485 84.24 82.755 ;
     RECT  2.16 83.025 84.24 83.295 ;
     RECT  2.16 83.565 84.24 83.835 ;
     RECT  2.16 84.105 84.24 84.24 ;
    LAYER RVTP ;
     RECT  2.16 2.295 84.24 2.565 ;
     RECT  2.16 2.835 84.24 3.105 ;
     RECT  2.16 3.375 84.24 3.645 ;
     RECT  2.16 3.915 84.24 4.185 ;
     RECT  2.16 4.455 84.24 4.725 ;
     RECT  2.16 4.995 84.24 5.265 ;
     RECT  2.16 5.535 84.24 5.805 ;
     RECT  2.16 6.075 84.24 6.345 ;
     RECT  2.16 6.615 84.24 6.885 ;
     RECT  2.16 7.155 84.24 7.425 ;
     RECT  2.16 7.695 84.24 7.965 ;
     RECT  2.16 8.235 84.24 8.505 ;
     RECT  2.16 8.775 84.24 9.045 ;
     RECT  2.16 9.315 84.24 9.585 ;
     RECT  2.16 9.855 84.24 10.125 ;
     RECT  2.16 10.395 84.24 10.665 ;
     RECT  2.16 10.935 84.24 11.205 ;
     RECT  2.16 11.475 84.24 11.745 ;
     RECT  2.16 12.015 84.24 12.285 ;
     RECT  2.16 12.555 84.24 12.825 ;
     RECT  2.16 13.095 84.24 13.365 ;
     RECT  2.16 13.635 84.24 13.905 ;
     RECT  2.16 14.175 84.24 14.445 ;
     RECT  2.16 14.715 84.24 14.985 ;
     RECT  2.16 15.255 84.24 15.525 ;
     RECT  2.16 15.795 84.24 16.065 ;
     RECT  2.16 16.335 84.24 16.605 ;
     RECT  2.16 16.875 84.24 17.145 ;
     RECT  2.16 17.415 84.24 17.685 ;
     RECT  2.16 17.955 84.24 18.225 ;
     RECT  2.16 18.495 84.24 18.765 ;
     RECT  2.16 19.035 84.24 19.305 ;
     RECT  2.16 19.575 84.24 19.845 ;
     RECT  2.16 20.115 84.24 20.385 ;
     RECT  2.16 20.655 84.24 20.925 ;
     RECT  2.16 21.195 84.24 21.465 ;
     RECT  2.16 21.735 84.24 22.005 ;
     RECT  2.16 22.275 84.24 22.545 ;
     RECT  2.16 22.815 84.24 23.085 ;
     RECT  2.16 23.355 84.24 23.625 ;
     RECT  2.16 23.895 84.24 24.165 ;
     RECT  2.16 24.435 84.24 24.705 ;
     RECT  2.16 24.975 84.24 25.245 ;
     RECT  2.16 25.515 84.24 25.785 ;
     RECT  2.16 26.055 84.24 26.325 ;
     RECT  2.16 26.595 84.24 26.865 ;
     RECT  2.16 27.135 84.24 27.405 ;
     RECT  2.16 27.675 84.24 27.945 ;
     RECT  2.16 28.215 84.24 28.485 ;
     RECT  2.16 28.755 84.24 29.025 ;
     RECT  2.16 29.295 84.24 29.565 ;
     RECT  2.16 29.835 84.24 30.105 ;
     RECT  2.16 30.375 84.24 30.645 ;
     RECT  2.16 30.915 84.24 31.185 ;
     RECT  2.16 31.455 84.24 31.725 ;
     RECT  2.16 31.995 84.24 32.265 ;
     RECT  2.16 32.535 84.24 32.805 ;
     RECT  2.16 33.075 84.24 33.345 ;
     RECT  2.16 33.615 84.24 33.885 ;
     RECT  2.16 34.155 84.24 34.425 ;
     RECT  2.16 34.695 84.24 34.965 ;
     RECT  2.16 35.235 84.24 35.505 ;
     RECT  2.16 35.775 84.24 36.045 ;
     RECT  2.16 36.315 84.24 36.585 ;
     RECT  2.16 36.855 84.24 37.125 ;
     RECT  2.16 37.395 84.24 37.665 ;
     RECT  2.16 37.935 84.24 38.205 ;
     RECT  2.16 38.475 84.24 38.745 ;
     RECT  2.16 39.015 84.24 39.285 ;
     RECT  2.16 39.555 84.24 39.825 ;
     RECT  2.16 40.095 84.24 40.365 ;
     RECT  2.16 40.635 84.24 40.905 ;
     RECT  2.16 41.175 84.24 41.445 ;
     RECT  2.16 41.715 84.24 41.985 ;
     RECT  2.16 42.255 84.24 42.525 ;
     RECT  2.16 42.795 84.24 43.065 ;
     RECT  2.16 43.335 84.24 43.605 ;
     RECT  2.16 43.875 84.24 44.145 ;
     RECT  2.16 44.415 84.24 44.685 ;
     RECT  2.16 44.955 84.24 45.225 ;
     RECT  2.16 45.495 84.24 45.765 ;
     RECT  2.16 46.035 84.24 46.305 ;
     RECT  2.16 46.575 84.24 46.845 ;
     RECT  2.16 47.115 84.24 47.385 ;
     RECT  2.16 47.655 84.24 47.925 ;
     RECT  2.16 48.195 84.24 48.465 ;
     RECT  2.16 48.735 84.24 49.005 ;
     RECT  2.16 49.275 84.24 49.545 ;
     RECT  2.16 49.815 84.24 50.085 ;
     RECT  2.16 50.355 84.24 50.625 ;
     RECT  2.16 50.895 84.24 51.165 ;
     RECT  2.16 51.435 84.24 51.705 ;
     RECT  2.16 51.975 84.24 52.245 ;
     RECT  2.16 52.515 84.24 52.785 ;
     RECT  2.16 53.055 84.24 53.325 ;
     RECT  2.16 53.595 84.24 53.865 ;
     RECT  2.16 54.135 84.24 54.405 ;
     RECT  2.16 54.675 84.24 54.945 ;
     RECT  2.16 55.215 84.24 55.485 ;
     RECT  2.16 55.755 84.24 56.025 ;
     RECT  2.16 56.295 84.24 56.565 ;
     RECT  2.16 56.835 84.24 57.105 ;
     RECT  2.16 57.375 84.24 57.645 ;
     RECT  2.16 57.915 84.24 58.185 ;
     RECT  2.16 58.455 84.24 58.725 ;
     RECT  2.16 58.995 84.24 59.265 ;
     RECT  2.16 59.535 84.24 59.805 ;
     RECT  2.16 60.075 84.24 60.345 ;
     RECT  2.16 60.615 84.24 60.885 ;
     RECT  2.16 61.155 84.24 61.425 ;
     RECT  2.16 61.695 84.24 61.965 ;
     RECT  2.16 62.235 84.24 62.505 ;
     RECT  2.16 62.775 84.24 63.045 ;
     RECT  2.16 63.315 84.24 63.585 ;
     RECT  2.16 63.855 84.24 64.125 ;
     RECT  2.16 64.395 84.24 64.665 ;
     RECT  2.16 64.935 84.24 65.205 ;
     RECT  2.16 65.475 84.24 65.745 ;
     RECT  2.16 66.015 84.24 66.285 ;
     RECT  2.16 66.555 84.24 66.825 ;
     RECT  2.16 67.095 84.24 67.365 ;
     RECT  2.16 67.635 84.24 67.905 ;
     RECT  2.16 68.175 84.24 68.445 ;
     RECT  2.16 68.715 84.24 68.985 ;
     RECT  2.16 69.255 84.24 69.525 ;
     RECT  2.16 69.795 84.24 70.065 ;
     RECT  2.16 70.335 84.24 70.605 ;
     RECT  2.16 70.875 84.24 71.145 ;
     RECT  2.16 71.415 84.24 71.685 ;
     RECT  2.16 71.955 84.24 72.225 ;
     RECT  2.16 72.495 84.24 72.765 ;
     RECT  2.16 73.035 84.24 73.305 ;
     RECT  2.16 73.575 84.24 73.845 ;
     RECT  2.16 74.115 84.24 74.385 ;
     RECT  2.16 74.655 84.24 74.925 ;
     RECT  2.16 75.195 84.24 75.465 ;
     RECT  2.16 75.735 84.24 76.005 ;
     RECT  2.16 76.275 84.24 76.545 ;
     RECT  2.16 76.815 84.24 77.085 ;
     RECT  2.16 77.355 84.24 77.625 ;
     RECT  2.16 77.895 84.24 78.165 ;
     RECT  2.16 78.435 84.24 78.705 ;
     RECT  2.16 78.975 84.24 79.245 ;
     RECT  2.16 79.515 84.24 79.785 ;
     RECT  2.16 80.055 84.24 80.325 ;
     RECT  2.16 80.595 84.24 80.865 ;
     RECT  2.16 81.135 84.24 81.405 ;
     RECT  2.16 81.675 84.24 81.945 ;
     RECT  2.16 82.215 84.24 82.485 ;
     RECT  2.16 82.755 84.24 83.025 ;
     RECT  2.16 83.295 84.24 83.565 ;
     RECT  2.16 83.835 84.24 84.105 ;
    LAYER M1 ;
     RECT  2.16 2.151 84.24 84.249 ;
    LAYER M2 ;
     RECT  0.139 25.722 2.16 25.74 ;
     RECT  0.031 48.672 2.16 48.69 ;
     RECT  2.16 2.151 31.351 84.249 ;
     RECT  31.351 2.151 33.863 84.294 ;
     RECT  33.863 2.151 84.24 84.249 ;
     RECT  84.24 30.996 84.839 34.524 ;
     RECT  84.839 30.996 84.911 34.452 ;
     RECT  84.24 50.706 84.947 55.944 ;
     RECT  84.947 51.786 85.451 55.944 ;
     RECT  84.911 30.996 85.487 34.344 ;
     RECT  84.24 35.676 85.487 36.234 ;
     RECT  85.451 51.786 85.487 53.964 ;
     RECT  85.487 53.946 85.523 53.964 ;
     RECT  85.487 30.996 85.559 33.3 ;
     RECT  84.24 48.816 85.559 49.914 ;
     RECT  85.559 49.176 85.631 49.914 ;
     RECT  85.631 49.176 85.667 49.194 ;
     RECT  84.24 56.736 86.171 57.024 ;
     RECT  85.559 32.346 86.207 33.3 ;
     RECT  85.451 54.846 86.207 55.944 ;
     RECT  85.559 30.996 86.243 31.284 ;
     RECT  85.487 35.946 86.243 36.234 ;
     RECT  85.487 51.786 86.243 52.344 ;
     RECT  86.207 54.846 86.243 55.854 ;
     RECT  84.947 50.706 86.251 50.724 ;
     RECT  86.207 33.048 86.279 33.3 ;
     RECT  86.243 54.846 86.279 54.864 ;
     RECT  86.243 31.266 86.315 31.284 ;
     RECT  86.279 33.048 86.315 33.066 ;
     RECT  86.243 52.326 86.315 52.344 ;
     RECT  86.243 55.836 86.315 55.854 ;
     RECT  86.251 50.706 86.351 50.769 ;
     RECT  84.24 30.186 86.387 30.204 ;
     RECT  86.243 35.946 86.387 35.964 ;
     RECT  86.171 57.006 86.387 57.024 ;
    LAYER M3 ;
     RECT  43.308 0.091 43.326 1.723 ;
     RECT  43.308 1.723 43.866 2.371 ;
     RECT  2.415 2.143 2.505 2.413 ;
     RECT  7.815 2.143 7.905 2.413 ;
     RECT  13.215 2.143 13.305 2.413 ;
     RECT  18.615 2.143 18.705 2.413 ;
     RECT  24.015 2.143 24.105 2.413 ;
     RECT  29.415 2.143 29.505 2.413 ;
     RECT  34.815 2.143 34.905 2.413 ;
     RECT  40.215 2.143 40.305 2.413 ;
     RECT  45.615 2.143 45.705 2.413 ;
     RECT  51.015 2.143 51.105 2.413 ;
     RECT  56.415 2.143 56.505 2.413 ;
     RECT  61.815 2.143 61.905 2.413 ;
     RECT  67.215 2.143 67.305 2.413 ;
     RECT  72.615 2.143 72.705 2.413 ;
     RECT  78.015 2.143 78.105 2.413 ;
     RECT  83.415 2.143 83.505 2.413 ;
     RECT  43.308 2.371 43.902 2.569 ;
     RECT  43.308 2.569 44.226 2.911 ;
     RECT  43.308 2.911 44.298 3.037 ;
     RECT  42.696 3.037 44.298 3.065 ;
     RECT  42.696 3.065 43.362 3.437 ;
     RECT  44.208 3.065 44.298 3.749 ;
     RECT  44.208 3.749 44.226 3.839 ;
     RECT  42.912 3.437 43.362 3.955 ;
     RECT  42.912 3.955 43.722 3.983 ;
     RECT  43.128 3.983 43.722 4.109 ;
     RECT  41.832 3.181 41.85 25.195 ;
     RECT  41.616 25.195 41.85 25.241 ;
     RECT  0.108 25.099 0.126 25.291 ;
     RECT  43.128 4.109 43.326 25.321 ;
     RECT  42.804 25.321 43.326 25.439 ;
     RECT  42.804 25.439 43.29 25.555 ;
     RECT  0.108 25.291 0.162 25.627 ;
     RECT  0.036 25.627 0.162 25.745 ;
     RECT  42.768 25.555 43.29 25.825 ;
     RECT  9.252 25.861 9.27 26.249 ;
     RECT  83.415 2.413 83.697 30.145 ;
     RECT  83.415 30.145 83.862 30.451 ;
     RECT  82.836 30.451 83.862 30.955 ;
     RECT  86.364 30.181 86.382 30.991 ;
     RECT  82.656 30.955 83.898 31.495 ;
     RECT  86.22 30.991 86.382 31.531 ;
     RECT  56.415 2.413 56.697 32.161 ;
     RECT  78.015 2.413 78.297 32.341 ;
     RECT  82.656 31.495 84.114 32.341 ;
     RECT  81.504 32.305 81.522 32.431 ;
     RECT  82.368 32.341 84.114 32.431 ;
     RECT  81.504 32.431 84.114 32.459 ;
     RECT  78.015 32.341 78.678 32.495 ;
     RECT  85.5 31.531 86.382 32.525 ;
     RECT  54.18 25.447 54.198 32.701 ;
     RECT  82.044 32.459 84.114 33.035 ;
     RECT  85.5 32.525 86.31 33.197 ;
     RECT  53.244 32.305 53.262 33.277 ;
     RECT  54.18 32.701 54.522 33.277 ;
     RECT  78.015 32.495 78.297 33.277 ;
     RECT  86.256 33.197 86.31 33.293 ;
     RECT  48.456 31.891 48.474 33.313 ;
     RECT  82.44 33.035 84.114 33.349 ;
     RECT  82.44 33.349 84.366 33.355 ;
     RECT  82.44 33.355 85.482 33.377 ;
     RECT  83.268 33.377 85.482 33.581 ;
     RECT  78.015 33.277 78.678 33.917 ;
     RECT  81.072 32.467 81.09 33.925 ;
     RECT  82.44 33.377 82.494 33.925 ;
     RECT  81.072 33.925 82.494 34.079 ;
     RECT  45.615 2.413 45.897 34.087 ;
     RECT  40.215 2.413 40.497 34.123 ;
     RECT  82.224 34.079 82.494 34.123 ;
     RECT  83.268 33.581 83.898 34.123 ;
     RECT  86.256 33.293 86.274 34.507 ;
     RECT  84.816 33.581 85.482 34.529 ;
     RECT  86.256 34.507 86.31 34.603 ;
     RECT  86.22 34.603 86.31 34.699 ;
     RECT  82.224 34.123 83.898 34.735 ;
     RECT  82.224 34.735 84.006 34.891 ;
     RECT  82.08 34.891 84.006 34.997 ;
     RECT  55.908 32.161 56.697 35.401 ;
     RECT  78.015 33.917 78.297 35.401 ;
     RECT  48.456 33.313 48.762 35.437 ;
     RECT  78.015 35.401 78.678 35.537 ;
     RECT  85.464 34.529 85.482 35.699 ;
     RECT  82.368 34.997 84.006 35.815 ;
     RECT  41.832 25.241 41.85 35.845 ;
     RECT  42.624 25.825 43.29 35.845 ;
     RECT  82.152 35.815 84.006 35.969 ;
     RECT  86.22 34.699 86.382 35.969 ;
     RECT  51.015 2.413 51.297 35.977 ;
     RECT  52.056 30.271 52.074 35.977 ;
     RECT  48.456 35.437 48.87 36.013 ;
     RECT  41.832 35.845 43.29 36.173 ;
     RECT  86.22 35.969 86.238 36.239 ;
     RECT  82.368 35.969 84.006 36.275 ;
     RECT  82.368 36.275 83.697 36.509 ;
     RECT  82.692 36.509 83.697 37.319 ;
     RECT  47.664 34.897 47.682 46.741 ;
     RECT  48.456 36.013 49.086 46.741 ;
     RECT  51.015 35.977 52.074 46.741 ;
     RECT  53.244 33.277 54.522 46.741 ;
     RECT  47.664 46.741 49.266 46.769 ;
     RECT  51.015 46.741 52.146 46.841 ;
     RECT  51.015 46.841 51.297 48.361 ;
     RECT  52.02 46.841 52.146 48.361 ;
     RECT  82.62 37.471 82.638 48.361 ;
     RECT  34.815 2.413 35.097 48.397 ;
     RECT  35.928 48.271 35.946 48.397 ;
     RECT  34.815 48.397 35.946 48.427 ;
     RECT  37.188 48.271 37.206 48.427 ;
     RECT  34.815 48.427 37.206 48.505 ;
     RECT  0.036 25.745 0.054 48.695 ;
     RECT  82.584 48.361 82.638 48.775 ;
     RECT  34.815 48.505 37.458 48.811 ;
     RECT  42.624 36.173 43.29 48.811 ;
     RECT  82.512 48.775 82.638 48.811 ;
     RECT  83.415 37.319 83.697 48.811 ;
     RECT  85.536 48.811 85.554 48.901 ;
     RECT  82.512 48.811 83.697 48.937 ;
     RECT  55.908 35.401 56.934 49.037 ;
     RECT  34.416 48.811 37.926 49.081 ;
     RECT  41.832 36.173 41.85 49.081 ;
     RECT  42.624 48.811 43.326 49.081 ;
     RECT  85.5 48.901 85.554 49.171 ;
     RECT  34.416 49.081 38.646 49.199 ;
     RECT  40.215 34.123 40.626 49.199 ;
     RECT  82.512 48.937 83.79 49.207 ;
     RECT  41.832 49.081 43.326 49.271 ;
     RECT  81.072 34.079 81.09 49.279 ;
     RECT  34.74 49.199 38.646 49.315 ;
     RECT  39.42 49.279 39.438 49.315 ;
     RECT  34.74 49.315 39.438 49.351 ;
     RECT  40.215 49.199 40.497 49.351 ;
     RECT  43.128 49.271 43.326 49.351 ;
     RECT  82.512 49.207 83.862 49.469 ;
     RECT  34.74 49.351 40.497 49.505 ;
     RECT  81.072 49.279 81.666 49.747 ;
     RECT  81.072 49.747 81.702 49.919 ;
     RECT  58.14 32.467 58.158 50.287 ;
     RECT  78.015 35.537 78.297 50.287 ;
     RECT  48.564 46.769 49.266 50.395 ;
     RECT  78.015 50.287 78.678 50.423 ;
     RECT  34.815 49.505 40.497 50.431 ;
     RECT  41.832 49.271 41.85 50.431 ;
     RECT  47.736 46.769 47.754 50.431 ;
     RECT  48.564 50.395 49.374 50.431 ;
     RECT  51.015 48.361 52.146 50.431 ;
     RECT  82.512 49.469 83.826 50.431 ;
     RECT  34.815 50.431 41.994 50.539 ;
     RECT  43.128 49.351 43.83 50.539 ;
     RECT  50.724 50.431 52.146 50.629 ;
     RECT  47.628 50.431 49.374 50.701 ;
     RECT  50.292 50.629 52.146 50.701 ;
     RECT  53.244 46.741 54.594 50.701 ;
     RECT  85.5 49.171 85.662 50.701 ;
     RECT  85.5 50.701 86.346 50.774 ;
     RECT  45 34.087 45.897 50.827 ;
     RECT  47.592 50.701 54.594 50.863 ;
     RECT  34.815 50.539 43.83 50.899 ;
     RECT  47.592 50.863 54.846 50.899 ;
     RECT  33.876 50.827 33.894 50.935 ;
     RECT  45 50.827 46.062 50.935 ;
     RECT  47.376 50.899 54.846 50.963 ;
     RECT  33.696 50.935 33.894 50.971 ;
     RECT  34.776 50.899 43.83 50.971 ;
     RECT  81.072 49.919 81.666 50.971 ;
     RECT  82.512 50.431 83.898 50.971 ;
     RECT  57.996 50.287 58.158 51.061 ;
     RECT  55.98 49.037 56.934 51.133 ;
     RECT  48.456 50.963 54.846 51.169 ;
     RECT  55.98 51.133 57.114 51.169 ;
     RECT  32.544 50.935 32.742 51.205 ;
     RECT  45 50.935 46.35 51.205 ;
     RECT  48.456 51.169 57.114 51.205 ;
     RECT  57.996 51.061 58.194 51.205 ;
     RECT  59.4 51.061 59.418 51.205 ;
     RECT  44.748 51.205 46.35 51.241 ;
     RECT  32.112 51.205 32.742 51.259 ;
     RECT  33.696 50.971 43.83 51.259 ;
     RECT  85.5 50.774 86.274 51.331 ;
     RECT  32.112 51.259 43.83 51.359 ;
     RECT  44.748 51.241 46.494 51.475 ;
     RECT  47.376 50.963 47.718 51.475 ;
     RECT  32.544 51.359 43.83 51.511 ;
     RECT  81.072 50.971 83.898 51.511 ;
     RECT  32.544 51.511 43.902 51.601 ;
     RECT  44.748 51.475 47.718 51.601 ;
     RECT  81.072 51.511 84.006 51.637 ;
     RECT  80.964 51.637 84.006 51.677 ;
     RECT  48.456 51.205 59.418 51.773 ;
     RECT  32.544 51.601 47.718 51.781 ;
     RECT  48.456 51.773 49.302 51.781 ;
     RECT  84.924 51.331 86.274 51.821 ;
     RECT  31.464 51.475 31.806 52.051 ;
     RECT  81.072 51.677 84.006 52.051 ;
     RECT  84.924 51.821 85.482 52.051 ;
     RECT  32.544 51.781 49.302 52.079 ;
     RECT  81.072 52.051 85.482 52.109 ;
     RECT  50.184 51.773 59.418 52.141 ;
     RECT  60.264 52.051 60.966 52.141 ;
     RECT  44.712 52.079 49.302 52.169 ;
     RECT  81.072 52.109 84.402 52.205 ;
     RECT  86.22 51.821 86.274 52.301 ;
     RECT  30.996 52.051 31.806 52.411 ;
     RECT  32.544 52.079 43.83 52.411 ;
     RECT  86.292 52.321 86.31 52.493 ;
     RECT  50.184 52.141 60.966 52.555 ;
     RECT  61.815 2.413 62.097 52.555 ;
     RECT  50.184 52.555 62.097 52.717 ;
     RECT  45 52.169 49.302 52.753 ;
     RECT  50.04 52.717 62.097 52.753 ;
     RECT  30.996 52.411 43.83 52.825 ;
     RECT  30.996 52.825 43.866 52.889 ;
     RECT  85.428 52.109 85.482 52.939 ;
     RECT  81.072 52.205 84.042 53.069 ;
     RECT  85.428 52.939 85.518 53.131 ;
     RECT  31.032 52.889 43.866 53.179 ;
     RECT  45 52.753 62.097 53.179 ;
     RECT  31.032 53.179 62.097 53.249 ;
     RECT  31.032 53.249 44.046 53.405 ;
     RECT  86.256 53.419 86.274 53.707 ;
     RECT  44.784 53.249 62.097 53.825 ;
     RECT  81.072 53.069 83.826 53.869 ;
     RECT  84.888 53.131 85.518 53.933 ;
     RECT  85.392 53.933 85.518 53.995 ;
     RECT  86.256 53.707 86.31 53.995 ;
     RECT  81.072 53.869 83.934 54.059 ;
     RECT  85.392 53.995 86.31 54.059 ;
     RECT  31.464 53.405 44.046 54.139 ;
     RECT  44.784 53.825 47.79 54.139 ;
     RECT  85.428 54.059 86.31 54.475 ;
     RECT  78.015 50.423 78.297 54.481 ;
     RECT  85.428 54.475 86.382 54.599 ;
     RECT  31.464 54.139 47.79 54.667 ;
     RECT  31.356 54.667 47.79 54.715 ;
     RECT  48.528 53.825 62.097 54.715 ;
     RECT  24.015 2.413 24.297 55.021 ;
     RECT  31.356 54.715 62.097 55.021 ;
     RECT  81.072 54.059 81.09 55.219 ;
     RECT  81.9 54.059 83.934 55.219 ;
     RECT  30.78 55.021 62.097 55.247 ;
     RECT  81.072 55.219 83.934 55.409 ;
     RECT  78.015 54.481 78.678 55.417 ;
     RECT  78.015 55.417 78.75 55.517 ;
     RECT  85.464 54.599 86.382 55.679 ;
     RECT  31.428 55.247 62.097 56.101 ;
     RECT  31.428 56.101 62.982 56.333 ;
     RECT  31.428 56.333 62.766 56.363 ;
     RECT  31.428 56.363 62.097 56.371 ;
     RECT  31.392 56.371 62.097 56.525 ;
     RECT  31.392 56.525 53.55 56.641 ;
     RECT  81.072 55.409 81.09 56.641 ;
     RECT  81.9 55.409 83.934 56.641 ;
     RECT  81.072 56.641 83.934 56.759 ;
     RECT  86.148 55.679 86.382 56.759 ;
     RECT  31.104 56.641 53.55 56.795 ;
     RECT  81.936 56.759 83.934 56.795 ;
     RECT  86.364 56.759 86.382 57.029 ;
     RECT  78.015 55.517 78.297 57.181 ;
     RECT  39.996 56.795 53.55 57.271 ;
     RECT  54.324 56.525 62.097 57.271 ;
     RECT  78.015 57.181 78.678 57.299 ;
     RECT  39.996 57.271 62.097 57.605 ;
     RECT  31.104 56.795 39.258 57.649 ;
     RECT  39.996 57.605 43.83 57.649 ;
     RECT  44.712 57.605 62.097 57.721 ;
     RECT  81.936 56.795 83.697 57.749 ;
     RECT  44.712 57.721 62.226 57.869 ;
     RECT  44.712 57.869 62.154 58.019 ;
     RECT  31.104 57.649 43.83 58.621 ;
     RECT  44.712 58.019 60.534 58.621 ;
     RECT  61.308 58.019 62.154 58.765 ;
     RECT  27.864 58.891 27.882 58.963 ;
     RECT  27.576 58.963 27.882 59.035 ;
     RECT  29.415 2.413 29.697 59.035 ;
     RECT  31.104 58.621 60.534 59.035 ;
     RECT  28.764 59.035 29.697 59.071 ;
     RECT  31.068 59.035 60.534 59.071 ;
     RECT  27.396 59.035 27.882 59.161 ;
     RECT  28.764 59.071 29.754 59.161 ;
     RECT  30.888 59.071 60.534 59.161 ;
     RECT  61.308 58.765 62.19 59.161 ;
     RECT  27.396 59.161 29.754 59.179 ;
     RECT  27.396 59.179 30.078 59.197 ;
     RECT  27.288 59.197 30.078 59.227 ;
     RECT  30.888 59.161 62.19 59.233 ;
     RECT  26.712 59.227 30.078 59.341 ;
     RECT  30.888 59.233 62.514 59.341 ;
     RECT  26.712 59.341 62.514 59.459 ;
     RECT  26.712 59.459 62.262 59.503 ;
     RECT  26.316 59.503 62.262 59.611 ;
     RECT  26.244 59.611 62.262 59.765 ;
     RECT  81.072 56.759 81.09 60.449 ;
     RECT  26.244 59.765 62.097 60.511 ;
     RECT  26.028 60.511 62.097 61.079 ;
     RECT  24.015 55.021 24.534 61.195 ;
     RECT  9.36 26.401 9.378 61.259 ;
     RECT  55.62 61.079 62.097 61.393 ;
     RECT  62.892 61.321 62.91 61.393 ;
     RECT  55.62 61.393 62.91 61.429 ;
     RECT  24.015 61.195 25.146 61.465 ;
     RECT  26.028 61.079 54.702 61.465 ;
     RECT  55.62 61.429 63.198 61.529 ;
     RECT  59.436 61.529 63.198 61.663 ;
     RECT  24.015 61.465 54.702 61.723 ;
     RECT  23.976 61.723 54.702 61.969 ;
     RECT  55.62 61.529 58.698 61.969 ;
     RECT  59.436 61.663 63.63 62.159 ;
     RECT  59.436 62.159 63.486 62.303 ;
     RECT  23.976 61.969 58.698 62.311 ;
     RECT  59.436 62.303 63.306 62.311 ;
     RECT  81.936 57.749 82.674 62.339 ;
     RECT  23.976 62.311 63.306 62.731 ;
     RECT  23.904 62.731 63.306 63.005 ;
     RECT  24.015 63.005 63.306 63.067 ;
     RECT  24.015 63.067 63.558 63.211 ;
     RECT  24.015 63.211 63.81 63.389 ;
     RECT  39.924 63.389 63.81 63.581 ;
     RECT  22.824 62.545 22.842 63.787 ;
     RECT  24.015 63.389 39.186 63.787 ;
     RECT  22.716 63.787 39.186 64.165 ;
     RECT  39.924 63.581 63.738 64.165 ;
     RECT  82.62 62.339 82.674 64.229 ;
     RECT  22.716 64.165 63.738 64.669 ;
     RECT  22.536 64.669 63.738 65.407 ;
     RECT  22.5 65.407 63.738 66.361 ;
     RECT  22.5 66.361 63.954 67.199 ;
     RECT  42.732 67.199 63.954 67.243 ;
     RECT  21.672 65.011 21.69 67.441 ;
     RECT  20.628 67.441 21.69 67.483 ;
     RECT  22.5 67.199 41.922 67.483 ;
     RECT  19.656 67.435 19.674 67.531 ;
     RECT  20.628 67.483 41.922 67.531 ;
     RECT  19.656 67.531 41.922 67.559 ;
     RECT  42.732 67.243 64.062 67.711 ;
     RECT  20.016 67.559 41.922 67.945 ;
     RECT  42.732 67.711 64.422 67.945 ;
     RECT  82.656 64.229 82.674 67.973 ;
     RECT  20.016 67.945 64.458 68.251 ;
     RECT  20.016 68.251 64.53 68.279 ;
     RECT  23.724 68.279 64.53 68.369 ;
     RECT  23.724 68.369 64.422 68.405 ;
     RECT  20.016 68.279 22.914 68.549 ;
     RECT  18.615 2.413 18.897 68.791 ;
     RECT  20.016 68.549 22.842 68.791 ;
     RECT  18.615 68.791 22.842 69.295 ;
     RECT  23.724 68.405 64.17 69.295 ;
     RECT  18.615 69.295 22.878 69.331 ;
     RECT  23.616 69.295 64.17 69.331 ;
     RECT  18.615 69.331 64.17 69.449 ;
     RECT  19.656 69.449 64.098 69.533 ;
     RECT  20.232 69.533 64.098 69.899 ;
     RECT  20.232 69.899 63.99 70.339 ;
     RECT  20.196 70.339 63.99 70.375 ;
     RECT  18.615 69.449 18.897 70.459 ;
     RECT  19.944 70.375 63.99 70.459 ;
     RECT  18.615 70.459 63.99 70.681 ;
     RECT  18.615 70.681 64.314 71.069 ;
     RECT  18.615 71.069 63.99 71.105 ;
     RECT  18.615 71.105 63.594 71.261 ;
     RECT  19.908 71.261 63.594 71.339 ;
     RECT  19.944 71.339 63.594 71.645 ;
     RECT  20.052 71.645 63.594 71.915 ;
     RECT  20.124 71.915 63.594 72.841 ;
     RECT  18.615 71.261 18.897 72.907 ;
     RECT  20.052 72.841 63.594 72.907 ;
     RECT  18.615 72.907 63.594 72.959 ;
     RECT  19.944 72.959 59.13 73.535 ;
     RECT  59.868 72.959 63.594 74.317 ;
     RECT  19.944 73.535 58.878 74.353 ;
     RECT  19.944 74.353 59.058 74.461 ;
     RECT  59.868 74.317 63.702 74.461 ;
     RECT  19.944 74.461 63.702 74.551 ;
     RECT  19.944 74.551 64.242 74.579 ;
     RECT  19.8 74.587 19.818 74.669 ;
     RECT  20.556 74.579 64.242 74.957 ;
     RECT  20.556 74.957 63.702 75.433 ;
     RECT  20.376 75.433 63.702 75.541 ;
     RECT  20.304 75.541 63.702 75.659 ;
     RECT  20.7 75.659 63.702 76.199 ;
     RECT  19.944 75.703 19.962 76.397 ;
     RECT  20.808 76.199 63.702 76.505 ;
     RECT  20.916 76.505 63.702 76.711 ;
     RECT  20.916 76.711 63.774 77.279 ;
     RECT  20.916 77.279 63.666 77.309 ;
     RECT  63.648 77.309 63.666 77.315 ;
     RECT  20.916 77.309 62.478 77.431 ;
     RECT  20.592 77.431 62.478 77.515 ;
     RECT  20.196 77.515 62.478 77.549 ;
     RECT  20.196 77.549 20.214 77.555 ;
     RECT  21.132 77.549 62.478 77.819 ;
     RECT  21.132 77.819 62.37 77.855 ;
     RECT  21.132 77.855 62.097 78.637 ;
     RECT  20.592 78.637 62.097 78.667 ;
     RECT  20.412 78.667 62.097 78.935 ;
     RECT  20.412 78.935 37.242 79.583 ;
     RECT  21.204 79.583 37.242 79.709 ;
     RECT  20.412 79.583 20.43 79.745 ;
     RECT  55.044 78.935 62.097 79.745 ;
     RECT  38.088 78.935 54.306 79.789 ;
     RECT  55.044 79.745 59.274 79.789 ;
     RECT  21.348 79.709 37.242 79.825 ;
     RECT  21.348 79.825 37.314 79.861 ;
     RECT  38.088 79.789 59.274 79.861 ;
     RECT  21.348 79.861 59.274 79.979 ;
     RECT  60.012 79.745 62.097 79.979 ;
     RECT  21.348 79.979 21.366 80.015 ;
     RECT  60.048 79.979 62.097 80.555 ;
     RECT  60.048 80.555 61.002 80.627 ;
     RECT  22.104 79.979 59.274 80.825 ;
     RECT  22.104 80.825 22.626 80.869 ;
     RECT  23.364 80.825 59.274 80.905 ;
     RECT  60.048 80.627 60.822 80.905 ;
     RECT  21.888 80.869 22.626 81.059 ;
     RECT  22.14 81.059 22.626 81.203 ;
     RECT  22.212 81.203 22.626 81.329 ;
     RECT  23.364 80.905 60.822 81.437 ;
     RECT  22.32 81.329 22.626 81.509 ;
     RECT  22.608 81.509 22.626 81.607 ;
     RECT  23.364 81.437 37.458 81.607 ;
     RECT  22.608 81.607 37.458 81.677 ;
     RECT  48.096 81.437 60.822 81.779 ;
     RECT  23.868 81.677 37.458 82.049 ;
     RECT  48.096 81.779 60.318 82.049 ;
     RECT  23.94 82.049 37.458 82.255 ;
     RECT  38.196 81.437 47.178 82.255 ;
     RECT  48.096 82.049 60.282 82.255 ;
     RECT  48.06 82.255 60.282 82.417 ;
     RECT  23.94 82.255 47.178 82.561 ;
     RECT  47.952 82.417 60.282 82.561 ;
     RECT  23.94 82.561 60.282 82.679 ;
     RECT  23.94 82.679 60.138 82.715 ;
     RECT  24.015 82.715 60.138 83.219 ;
     RECT  24.015 83.219 40.878 83.255 ;
     RECT  42.264 83.219 60.138 83.255 ;
     RECT  42.516 83.255 60.138 83.327 ;
     RECT  57.42 83.327 60.138 83.399 ;
     RECT  26.028 83.255 40.878 83.489 ;
     RECT  28.224 83.489 40.698 83.597 ;
     RECT  26.172 83.489 27.486 83.633 ;
     RECT  57.42 83.399 59.706 83.633 ;
     RECT  58.392 83.633 59.706 83.669 ;
     RECT  26.28 83.633 27.486 83.759 ;
     RECT  28.224 83.597 40.626 83.759 ;
     RECT  42.66 83.327 56.697 83.759 ;
     RECT  58.392 83.669 59.13 83.759 ;
     RECT  26.28 83.759 27.378 83.795 ;
     RECT  28.476 83.759 35.766 83.795 ;
     RECT  36.756 83.759 40.626 83.795 ;
     RECT  42.912 83.759 56.697 83.795 ;
     RECT  58.464 83.759 59.13 83.795 ;
     RECT  58.644 83.795 58.662 83.867 ;
     RECT  24.015 83.255 25.146 83.939 ;
     RECT  42.912 83.795 52.686 83.939 ;
     RECT  53.532 83.795 56.697 83.939 ;
     RECT  2.415 2.413 2.697 83.987 ;
     RECT  7.815 2.413 8.097 83.987 ;
     RECT  13.215 2.413 13.497 83.987 ;
     RECT  18.615 72.959 18.897 83.987 ;
     RECT  24.015 83.939 24.297 83.987 ;
     RECT  28.476 83.795 29.697 83.987 ;
     RECT  55.764 83.939 56.697 83.987 ;
     RECT  61.815 80.555 62.097 83.987 ;
     RECT  67.215 2.413 67.497 83.987 ;
     RECT  72.615 2.413 72.897 83.987 ;
     RECT  78.015 57.299 78.297 83.987 ;
     RECT  83.415 57.749 83.697 83.987 ;
     RECT  26.28 83.795 26.298 84.029 ;
     RECT  30.492 83.795 35.766 84.029 ;
     RECT  37.08 83.795 40.626 84.029 ;
     RECT  42.912 83.939 43.47 84.029 ;
     RECT  44.244 83.939 52.686 84.029 ;
     RECT  53.532 83.939 55.026 84.029 ;
     RECT  57.42 83.633 57.438 84.029 ;
     RECT  30.708 84.029 35.622 84.065 ;
     RECT  37.08 84.029 37.962 84.065 ;
     RECT  38.952 84.029 40.305 84.065 ;
     RECT  42.912 84.029 43.362 84.065 ;
     RECT  53.604 84.029 55.026 84.065 ;
     RECT  55.764 83.987 56.505 84.065 ;
     RECT  49.392 84.029 52.47 84.077 ;
     RECT  37.08 84.065 37.746 84.137 ;
     RECT  49.392 84.077 52.29 84.137 ;
     RECT  53.604 84.065 54.09 84.137 ;
     RECT  55.008 84.065 55.026 84.137 ;
     RECT  44.244 84.029 48.15 84.173 ;
     RECT  25.128 83.939 25.146 84.209 ;
     RECT  28.476 83.987 29.505 84.209 ;
     RECT  37.728 84.137 37.746 84.209 ;
     RECT  49.392 84.137 51.966 84.209 ;
     RECT  53.604 84.137 53.622 84.209 ;
     RECT  56.304 84.065 56.505 84.209 ;
     RECT  30.708 84.065 35.55 84.221 ;
     RECT  44.244 84.173 44.37 84.221 ;
     RECT  2.415 83.987 2.505 84.257 ;
     RECT  7.815 83.987 7.905 84.257 ;
     RECT  13.215 83.987 13.305 84.257 ;
     RECT  18.615 83.987 18.705 84.257 ;
     RECT  24.015 83.987 24.105 84.257 ;
     RECT  29.415 84.209 29.505 84.257 ;
     RECT  40.215 84.065 40.305 84.257 ;
     RECT  49.392 84.209 51.105 84.257 ;
     RECT  56.415 84.209 56.505 84.257 ;
     RECT  61.815 83.987 61.905 84.257 ;
     RECT  67.215 83.987 67.305 84.257 ;
     RECT  72.615 83.987 72.705 84.257 ;
     RECT  78.015 83.987 78.105 84.257 ;
     RECT  83.415 83.987 83.505 84.257 ;
     RECT  30.78 84.221 35.55 84.365 ;
     RECT  45.18 84.173 48.15 84.365 ;
     RECT  49.392 84.257 50.598 84.365 ;
     RECT  51.912 84.209 51.966 84.365 ;
     RECT  45.18 84.365 45.558 84.413 ;
     RECT  45.18 84.413 45.198 84.989 ;
     RECT  28.476 84.209 28.494 85.517 ;
     RECT  33.624 84.365 35.55 85.517 ;
     RECT  44.352 84.221 44.37 85.565 ;
     RECT  48.348 85.771 48.366 85.949 ;
     RECT  33.84 85.517 35.55 86.141 ;
     RECT  33.84 86.141 34.65 86.189 ;
     RECT  34.38 86.189 34.65 86.237 ;
     RECT  35.532 86.141 35.55 86.237 ;
     RECT  46.332 84.365 47.034 86.251 ;
     RECT  30.78 84.365 32.346 86.285 ;
     RECT  34.38 86.237 34.398 86.285 ;
     RECT  46.332 86.251 47.106 86.285 ;
     RECT  49.932 86.059 49.95 86.285 ;
     RECT  51.912 84.365 51.93 86.285 ;
     RECT  42.912 84.065 42.93 86.381 ;
     RECT  47.088 86.285 47.106 86.381 ;
    LAYER M4 ;
     RECT  0.025 25.632 0.06 25.656 ;
     RECT  0.06 25.008 0.137 25.656 ;
     RECT  0.137 25.008 0.173 25.32 ;
     RECT  0.173 25.008 0.227 25.224 ;
     RECT  0.227 25.2 2.408 25.224 ;
     RECT  0.181 58.992 2.408 59.016 ;
     RECT  2.408 2.148 2.512 84.252 ;
     RECT  2.512 2.418 2.704 83.982 ;
     RECT  2.704 25.2 7.808 25.224 ;
     RECT  2.704 58.992 7.808 59.016 ;
     RECT  7.808 2.148 7.912 84.252 ;
     RECT  7.912 2.418 8.104 83.982 ;
     RECT  8.104 25.2 13.208 25.224 ;
     RECT  8.104 58.992 13.208 59.016 ;
     RECT  13.208 2.148 13.312 84.252 ;
     RECT  13.312 2.418 13.504 83.982 ;
     RECT  13.504 25.2 18.608 25.224 ;
     RECT  13.504 58.992 18.608 59.016 ;
     RECT  18.608 2.148 18.712 84.252 ;
     RECT  18.712 2.418 18.904 83.982 ;
     RECT  18.904 69.504 19.619 71.256 ;
     RECT  19.619 71.232 19.909 71.256 ;
     RECT  18.904 72.912 19.909 72.936 ;
     RECT  18.904 74.64 19.909 74.664 ;
     RECT  19.909 71.232 19.933 72.936 ;
     RECT  19.909 74.64 19.933 75.096 ;
     RECT  19.933 71.232 19.955 75.096 ;
     RECT  19.955 71.856 20.016 73.8 ;
     RECT  20.016 71.856 20.081 72.36 ;
     RECT  19.933 76.368 20.197 76.392 ;
     RECT  20.156 77.52 20.197 77.544 ;
     RECT  20.197 76.368 20.243 77.544 ;
     RECT  18.904 67.44 20.617 67.464 ;
     RECT  19.619 69.504 20.869 69.528 ;
     RECT  20.869 69.168 20.941 69.528 ;
     RECT  20.243 76.368 20.945 77.016 ;
     RECT  20.941 69.168 21.557 70.44 ;
     RECT  21.557 69.168 21.809 69.72 ;
     RECT  20.197 78.672 21.841 78.696 ;
     RECT  21.841 78.672 22.093 79.464 ;
     RECT  22.093 78.672 22.097 80.376 ;
     RECT  20.016 73.776 22.277 73.8 ;
     RECT  19.955 75.072 22.309 75.096 ;
     RECT  22.309 75.072 22.31 75.144 ;
     RECT  21.809 69.312 22.313 69.72 ;
     RECT  22.31 75.12 22.381 75.144 ;
     RECT  22.097 79.2 22.597 80.376 ;
     RECT  20.081 72.336 22.633 72.36 ;
     RECT  22.597 79.2 22.681 81.672 ;
     RECT  20.617 67.44 22.741 67.512 ;
     RECT  22.741 67.44 22.781 67.56 ;
     RECT  22.381 75.12 22.781 75.672 ;
     RECT  22.633 71.904 22.889 72.36 ;
     RECT  22.781 67.536 23.281 67.56 ;
     RECT  23.281 67.536 23.353 67.608 ;
     RECT  23.353 67.536 23.857 67.704 ;
     RECT  22.781 75.12 23.857 75.144 ;
     RECT  22.313 69.696 23.893 69.72 ;
     RECT  23.101 72.96 23.893 73.08 ;
     RECT  23.857 75.12 23.893 76.488 ;
     RECT  23.821 70.848 24.001 70.872 ;
     RECT  18.904 25.2 24.008 25.224 ;
     RECT  18.904 58.992 24.008 59.016 ;
     RECT  23.965 61.728 24.008 61.752 ;
     RECT  23.893 62.736 24.008 62.76 ;
     RECT  22.705 63.792 24.008 63.816 ;
     RECT  24.001 65.472 24.008 65.496 ;
     RECT  23.857 66.576 24.008 67.704 ;
     RECT  23.893 69.696 24.008 69.816 ;
     RECT  24.001 70.8 24.008 70.872 ;
     RECT  23.893 72.144 24.008 73.08 ;
     RECT  23.893 74.688 24.008 76.488 ;
     RECT  22.681 79.2 24.008 80.376 ;
     RECT  22.681 81.6 24.008 81.672 ;
     RECT  24.008 2.148 24.112 84.252 ;
     RECT  24.112 2.418 24.304 83.982 ;
     RECT  24.304 78.192 24.419 79.464 ;
     RECT  24.304 71.232 24.563 74.664 ;
     RECT  24.563 71.232 24.581 71.832 ;
     RECT  24.304 75.792 24.581 77.208 ;
     RECT  24.304 64.896 24.761 67.608 ;
     RECT  24.304 81.6 24.905 81.624 ;
     RECT  24.761 64.896 25.013 67.176 ;
     RECT  25.013 64.896 25.139 65.928 ;
     RECT  24.581 76.464 25.193 77.208 ;
     RECT  25.139 65.472 25.265 65.928 ;
     RECT  25.193 76.464 25.373 76.536 ;
     RECT  24.419 78.192 25.445 79.224 ;
     RECT  24.304 61.44 25.477 61.752 ;
     RECT  24.304 62.736 25.477 63.72 ;
     RECT  24.563 74.64 25.657 74.664 ;
     RECT  25.477 61.44 25.661 63.72 ;
     RECT  25.657 74.64 25.661 75.192 ;
     RECT  24.304 68.64 25.805 69.864 ;
     RECT  25.373 76.512 25.841 76.536 ;
     RECT  24.563 73.056 25.909 73.512 ;
     RECT  25.909 73.008 25.913 73.512 ;
     RECT  25.265 65.904 25.949 65.928 ;
     RECT  25.013 67.152 25.949 67.176 ;
     RECT  26.012 81.456 26.053 81.48 ;
     RECT  26.053 81.072 26.099 81.48 ;
     RECT  26.017 82.656 26.101 82.68 ;
     RECT  25.661 61.44 26.125 62.664 ;
     RECT  26.125 60.96 26.165 62.664 ;
     RECT  24.581 71.76 26.273 71.832 ;
     RECT  26.165 60.96 26.389 61.944 ;
     RECT  26.233 82.512 26.525 82.536 ;
     RECT  24.304 58.992 26.701 59.016 ;
     RECT  25.445 79.152 26.701 79.224 ;
     RECT  25.805 68.64 26.737 69.576 ;
     RECT  26.389 60.384 26.741 61.944 ;
     RECT  25.913 73.008 26.813 73.08 ;
     RECT  25.661 75.168 26.813 75.192 ;
     RECT  26.741 60.432 26.885 61.944 ;
     RECT  26.701 79.152 26.885 79.512 ;
     RECT  26.737 67.68 26.957 69.576 ;
     RECT  26.885 79.152 27.025 79.32 ;
     RECT  25.661 63.696 27.133 63.72 ;
     RECT  26.701 58.992 27.317 59.256 ;
     RECT  27.133 63.264 27.349 63.72 ;
     RECT  26.099 81.072 27.349 81.096 ;
     RECT  26.273 71.76 27.353 71.784 ;
     RECT  27.349 62.448 27.395 64.2 ;
     RECT  26.813 73.008 27.425 73.032 ;
     RECT  26.957 67.824 27.497 69.576 ;
     RECT  25.585 77.52 27.596 77.544 ;
     RECT  27.596 76.896 27.637 77.544 ;
     RECT  27.025 79.008 27.637 79.32 ;
     RECT  27.637 76.896 27.683 79.32 ;
     RECT  26.885 60.432 27.713 61.464 ;
     RECT  27.713 60.432 27.781 61.224 ;
     RECT  27.683 78.336 27.877 79.32 ;
     RECT  27.349 80.448 27.877 81.096 ;
     RECT  27.395 64.176 27.889 64.2 ;
     RECT  27.853 74.352 27.889 74.376 ;
     RECT  27.877 78.336 27.923 81.096 ;
     RECT  27.923 78.336 27.929 79.8 ;
     RECT  27.929 78.672 28.037 79.8 ;
     RECT  27.673 65.952 28.177 65.976 ;
     RECT  27.923 81.072 28.181 81.096 ;
     RECT  28.177 65.952 28.268 66.696 ;
     RECT  27.497 67.824 28.268 68.664 ;
     RECT  27.781 60.048 28.289 61.224 ;
     RECT  28.268 65.952 28.355 68.664 ;
     RECT  28.355 67.44 28.501 68.664 ;
     RECT  28.141 69.984 28.501 70.008 ;
     RECT  27.317 58.992 28.645 59.016 ;
     RECT  28.753 82.032 28.789 82.056 ;
     RECT  27.313 83.568 28.789 83.592 ;
     RECT  27.889 64.176 28.825 64.92 ;
     RECT  28.355 65.952 28.825 65.976 ;
     RECT  27.889 73.296 29.005 74.616 ;
     RECT  28.393 75.84 29.005 75.864 ;
     RECT  28.789 82.032 29.005 83.592 ;
     RECT  27.395 62.448 29.077 62.472 ;
     RECT  29.005 73.296 29.113 75.864 ;
     RECT  28.037 78.672 29.116 79.032 ;
     RECT  29.116 78.624 29.293 79.032 ;
     RECT  24.304 25.2 29.408 25.224 ;
     RECT  28.645 58.992 29.408 59.208 ;
     RECT  28.289 60.24 29.408 61.224 ;
     RECT  29.077 62.448 29.408 62.568 ;
     RECT  28.825 64.176 29.408 65.976 ;
     RECT  28.501 67.44 29.408 70.008 ;
     RECT  27.529 71.232 29.408 71.256 ;
     RECT  29.113 72.96 29.408 75.864 ;
     RECT  29.293 78.624 29.408 79.224 ;
     RECT  29.005 82.032 29.408 83.784 ;
     RECT  29.408 2.148 29.512 84.252 ;
     RECT  29.512 2.418 29.704 83.982 ;
     RECT  29.704 64.128 29.873 70.872 ;
     RECT  29.704 72.192 30.089 76.152 ;
     RECT  30.089 75.12 30.233 76.152 ;
     RECT  29.704 78.624 30.233 80.136 ;
     RECT  29.704 62.448 30.305 62.472 ;
     RECT  30.233 75.504 30.341 76.152 ;
     RECT  30.233 78.624 30.377 79.032 ;
     RECT  30.089 72.192 30.485 74.136 ;
     RECT  29.704 61.2 30.563 61.224 ;
     RECT  29.704 81.504 30.697 83.832 ;
     RECT  28.465 85.488 30.705 85.512 ;
     RECT  29.704 58.992 30.769 59.208 ;
     RECT  30.697 60.384 30.769 61.08 ;
     RECT  30.233 80.112 30.769 80.136 ;
     RECT  30.697 81.504 30.769 84.216 ;
     RECT  30.341 76.128 30.805 76.152 ;
     RECT  29.704 77.328 30.805 77.352 ;
     RECT  30.769 80.112 30.881 84.216 ;
     RECT  30.881 80.112 30.889 80.664 ;
     RECT  30.805 76.128 30.901 77.352 ;
     RECT  30.485 72.96 30.917 74.136 ;
     RECT  30.881 81.648 31.021 84.216 ;
     RECT  29.873 64.128 31.061 65.496 ;
     RECT  29.873 66.96 31.129 70.872 ;
     RECT  31.129 66.96 31.196 71.832 ;
     RECT  31.196 66.672 31.283 71.832 ;
     RECT  30.901 76.128 31.349 77.976 ;
     RECT  31.349 76.56 31.381 77.976 ;
     RECT  30.377 79.008 31.381 79.032 ;
     RECT  30.769 58.992 31.475 61.08 ;
     RECT  31.381 76.56 31.477 79.032 ;
     RECT  30.889 80.112 31.477 80.424 ;
     RECT  31.283 67.2 31.493 71.832 ;
     RECT  31.475 61.056 31.516 61.08 ;
     RECT  31.493 67.2 31.565 67.272 ;
     RECT  31.021 81.648 31.601 84.312 ;
     RECT  31.601 81.936 31.637 84.312 ;
     RECT  30.917 73.968 31.705 74.136 ;
     RECT  31.475 58.992 31.709 59.736 ;
     RECT  31.493 68.88 31.777 71.832 ;
     RECT  30.917 72.96 31.777 72.984 ;
     RECT  31.633 62.112 31.861 62.136 ;
     RECT  31.861 62.112 31.907 63 ;
     RECT  31.705 73.968 31.907 74.664 ;
     RECT  31.637 82.08 32.051 84.312 ;
     RECT  31.777 68.88 32.069 72.984 ;
     RECT  31.709 58.992 32.101 59.112 ;
     RECT  31.565 67.2 32.105 67.224 ;
     RECT  31.477 76.56 32.147 80.424 ;
     RECT  32.147 79.2 32.197 80.424 ;
     RECT  31.061 64.128 32.209 64.968 ;
     RECT  32.197 79.2 32.243 80.952 ;
     RECT  31.021 53.376 32.425 53.4 ;
     RECT  32.209 64.128 32.425 65.256 ;
     RECT  30.705 85.488 32.435 86.28 ;
     RECT  32.051 84.192 32.453 84.312 ;
     RECT  32.389 56.304 32.461 56.328 ;
     RECT  32.425 53.04 32.465 53.4 ;
     RECT  32.425 64.128 32.533 65.496 ;
     RECT  31.907 74.592 32.537 74.664 ;
     RECT  32.533 64.128 32.605 66.072 ;
     RECT  32.243 80.928 32.609 80.952 ;
     RECT  31.907 62.4 32.641 63 ;
     RECT  31.345 54.672 32.677 54.696 ;
     RECT  32.461 55.68 32.677 56.328 ;
     RECT  32.147 76.56 32.725 78.072 ;
     RECT  32.725 75.936 32.812 78.072 ;
     RECT  32.677 54.672 32.825 56.328 ;
     RECT  32.051 82.08 32.857 83.112 ;
     RECT  32.812 76.368 32.861 78.072 ;
     RECT  32.069 72.144 32.893 72.984 ;
     RECT  32.537 74.592 32.893 74.616 ;
     RECT  32.069 68.88 33.037 71.016 ;
     RECT  32.893 72.144 33.037 74.616 ;
     RECT  33.037 68.88 33.059 74.616 ;
     RECT  32.825 54.672 33.061 54.696 ;
     RECT  32.101 58.656 33.073 59.112 ;
     RECT  32.821 60.384 33.073 60.408 ;
     RECT  33.059 68.88 33.1 72.36 ;
     RECT  32.605 64.128 33.109 66.744 ;
     RECT  32.861 76.368 33.113 77.88 ;
     RECT  32.857 81.888 33.253 83.112 ;
     RECT  32.641 62.4 33.257 63.096 ;
     RECT  33.109 64.128 33.365 67.176 ;
     RECT  32.453 84.192 33.395 84.36 ;
     RECT  32.101 51.264 33.401 51.288 ;
     RECT  33.289 80.304 33.401 80.328 ;
     RECT  33.073 58.656 33.433 60.408 ;
     RECT  33.257 62.448 33.437 63.096 ;
     RECT  33.437 62.544 33.469 63.096 ;
     RECT  33.059 74.592 33.473 74.616 ;
     RECT  31.093 57.312 33.493 57.336 ;
     RECT  33.433 58.608 33.493 60.408 ;
     RECT  32.435 86.208 33.541 86.28 ;
     RECT  32.465 53.04 33.545 53.064 ;
     RECT  33.061 54.096 33.545 54.696 ;
     RECT  33.365 64.416 33.545 67.176 ;
     RECT  33.1 68.88 33.545 72.168 ;
     RECT  33.545 66.192 33.577 67.176 ;
     RECT  33.493 57.312 33.58 60.408 ;
     RECT  33.541 86.112 33.613 86.28 ;
     RECT  33.253 81.888 33.637 83.208 ;
     RECT  33.637 81.456 33.683 83.208 ;
     RECT  33.58 57.312 33.689 57.336 ;
     RECT  33.577 66.192 33.689 67.848 ;
     RECT  33.395 84.24 33.761 84.36 ;
     RECT  33.613 85.488 33.925 86.28 ;
     RECT  33.689 66.384 34.045 67.848 ;
     RECT  33.545 68.88 34.045 70.968 ;
     RECT  33.58 58.464 34.069 60.408 ;
     RECT  34.028 61.392 34.069 61.416 ;
     RECT  33.113 76.368 34.225 77.496 ;
     RECT  33.925 78.48 34.225 78.504 ;
     RECT  33.761 84.24 34.229 84.312 ;
     RECT  33.545 72.144 34.261 72.168 ;
     RECT  33.059 73.488 34.261 73.512 ;
     RECT  34.225 76.368 34.369 78.504 ;
     RECT  33.683 83.088 34.405 83.208 ;
     RECT  34.229 84.24 34.405 84.252 ;
     RECT  33.469 62.544 34.441 63.336 ;
     RECT  33.925 85.392 34.445 86.28 ;
     RECT  34.445 85.488 34.489 86.28 ;
     RECT  33.545 64.416 34.657 65.16 ;
     RECT  33.649 80.256 34.657 80.28 ;
     RECT  33.683 81.456 34.657 81.48 ;
     RECT  34.261 72.144 34.685 73.512 ;
     RECT  34.045 66.384 34.693 70.968 ;
     RECT  34.685 72.144 34.693 74.088 ;
     RECT  34.369 76.368 34.693 78.696 ;
     RECT  34.489 86.064 34.697 86.28 ;
     RECT  34.117 51.216 34.801 51.24 ;
     RECT  33.577 52.464 34.801 52.824 ;
     RECT  34.693 76.224 34.801 78.696 ;
     RECT  29.704 25.2 34.808 25.224 ;
     RECT  34.801 51.216 34.808 52.824 ;
     RECT  33.545 54.096 34.808 54.12 ;
     RECT  32.825 55.68 34.808 56.328 ;
     RECT  34.765 57.312 34.808 57.336 ;
     RECT  34.069 58.464 34.808 61.416 ;
     RECT  34.441 62.448 34.808 63.336 ;
     RECT  34.657 64.416 34.808 65.208 ;
     RECT  34.693 66.384 34.808 74.088 ;
     RECT  34.801 75.504 34.808 79.224 ;
     RECT  34.657 80.256 34.808 81.48 ;
     RECT  34.405 83.088 34.808 84.252 ;
     RECT  34.808 2.148 34.912 84.252 ;
     RECT  34.912 2.418 35.104 83.982 ;
     RECT  35.104 58.416 35.219 59.256 ;
     RECT  35.104 69.216 35.219 72.84 ;
     RECT  34.697 86.112 35.219 86.28 ;
     RECT  35.219 72.144 35.237 72.84 ;
     RECT  35.104 60.432 35.309 67.848 ;
     RECT  35.219 86.112 35.309 86.232 ;
     RECT  35.104 52.032 35.381 52.824 ;
     RECT  35.309 60.432 35.381 62.808 ;
     RECT  35.104 75.264 35.381 76.968 ;
     RECT  35.381 60.432 35.411 62.76 ;
     RECT  35.411 61.824 35.453 62.76 ;
     RECT  35.309 63.84 35.555 67.848 ;
     RECT  35.309 86.208 35.561 86.232 ;
     RECT  35.219 58.416 35.597 59.016 ;
     RECT  35.381 75.264 35.603 75.528 ;
     RECT  35.381 76.56 35.603 76.968 ;
     RECT  35.104 73.92 35.641 74.088 ;
     RECT  35.597 58.464 35.705 59.016 ;
     RECT  35.104 78.096 35.891 81.048 ;
     RECT  35.641 73.92 35.921 73.944 ;
     RECT  35.891 78.48 35.932 80.28 ;
     RECT  35.555 63.84 35.957 65.544 ;
     RECT  35.932 78.48 35.993 78.696 ;
     RECT  35.104 55.248 36.035 57.432 ;
     RECT  36.035 56.736 36.076 57.432 ;
     RECT  35.104 48.432 36.133 48.456 ;
     RECT  35.104 82.32 36.14 82.632 ;
     RECT  35.104 83.76 36.14 83.784 ;
     RECT  35.381 52.176 36.205 52.824 ;
     RECT  35.237 72.672 36.277 72.84 ;
     RECT  35.957 65.184 36.281 65.544 ;
     RECT  36.277 72.384 36.317 72.84 ;
     RECT  35.993 78.576 36.353 78.696 ;
     RECT  35.555 67.248 36.461 67.848 ;
     RECT  36.133 48.432 36.469 49.368 ;
     RECT  35.104 50.688 36.469 50.712 ;
     RECT  35.453 62.448 36.529 62.76 ;
     RECT  35.957 63.84 36.529 63.864 ;
     RECT  36.469 48.432 36.533 50.712 ;
     RECT  36.533 48.432 36.556 50.52 ;
     RECT  36.556 48.432 36.677 49.848 ;
     RECT  35.705 58.992 36.709 59.016 ;
     RECT  36.461 67.248 36.713 67.8 ;
     RECT  36.353 78.624 36.713 78.696 ;
     RECT  36.529 62.448 36.781 63.864 ;
     RECT  36.035 55.248 36.853 55.272 ;
     RECT  35.411 60.432 36.857 60.456 ;
     RECT  36.205 52.176 36.929 53.016 ;
     RECT  36.853 54.864 36.997 55.272 ;
     RECT  35.603 76.56 36.997 76.584 ;
     RECT  36.677 49.344 37.001 49.848 ;
     RECT  36.929 52.224 37.037 53.016 ;
     RECT  36.781 62.4 37.073 63.864 ;
     RECT  36.709 58.992 37.141 59.16 ;
     RECT  36.997 54.096 37.177 55.272 ;
     RECT  35.932 80.256 37.181 80.28 ;
     RECT  36.076 57.312 37.213 57.432 ;
     RECT  36.713 78.624 37.253 78.648 ;
     RECT  36.281 65.184 37.357 65.4 ;
     RECT  37.177 54.096 37.393 55.608 ;
     RECT  37.393 54.048 37.465 55.608 ;
     RECT  35.219 69.216 37.465 70.872 ;
     RECT  36.317 72.384 37.465 72.696 ;
     RECT  35.603 75.264 37.501 75.288 ;
     RECT  36.997 76.56 37.501 76.728 ;
     RECT  36.713 67.344 37.537 67.8 ;
     RECT  37.465 69.216 37.537 72.696 ;
     RECT  37.213 56.832 37.573 57.432 ;
     RECT  37.141 58.416 37.573 59.16 ;
     RECT  37.073 63.12 37.573 63.864 ;
     RECT  37.357 65.184 37.573 65.64 ;
     RECT  37.501 75.264 37.573 76.728 ;
     RECT  37.537 67.344 37.577 72.696 ;
     RECT  37.573 63.12 37.619 65.64 ;
     RECT  37.573 74.592 37.619 76.728 ;
     RECT  37.465 54.048 37.685 55.704 ;
     RECT  37.577 68.4 37.685 72.696 ;
     RECT  37.685 54.048 37.721 55.608 ;
     RECT  37.619 74.592 37.757 74.616 ;
     RECT  37.619 75.84 37.865 76.728 ;
     RECT  37.001 49.584 37.889 49.848 ;
     RECT  36.14 82.32 37.901 83.784 ;
     RECT  37.889 49.584 37.973 50.76 ;
     RECT  37.901 82.416 37.973 83.784 ;
     RECT  37.685 69.216 38.005 72.696 ;
     RECT  37.393 62.016 38.041 62.04 ;
     RECT  37.619 63.12 38.041 63.144 ;
     RECT  37.577 67.344 38.077 67.368 ;
     RECT  37.573 56.832 38.081 59.16 ;
     RECT  37.037 52.992 38.149 53.016 ;
     RECT  38.081 56.832 38.149 59.016 ;
     RECT  37.619 64.704 38.293 65.64 ;
     RECT  38.077 67.056 38.293 67.368 ;
     RECT  38.149 52.416 38.333 53.016 ;
     RECT  38.293 64.704 38.333 67.368 ;
     RECT  37.973 49.584 38.405 50.424 ;
     RECT  38.333 52.416 38.581 52.776 ;
     RECT  38.149 60.96 38.581 60.984 ;
     RECT  38.041 62.016 38.581 63.144 ;
     RECT  37.865 75.984 38.585 76.728 ;
     RECT  38.581 62.016 38.617 63.528 ;
     RECT  38.333 64.704 38.617 64.968 ;
     RECT  38.005 69.216 38.62 73.032 ;
     RECT  37.721 54.048 38.657 54.888 ;
     RECT  38.581 51.744 38.689 52.776 ;
     RECT  38.585 76.368 38.689 76.728 ;
     RECT  38.657 54.72 38.725 54.888 ;
     RECT  38.689 76.368 38.729 76.776 ;
     RECT  38.617 62.016 38.771 64.968 ;
     RECT  38.729 76.512 38.797 76.776 ;
     RECT  38.581 60.528 38.801 60.984 ;
     RECT  38.725 54.72 38.829 55.272 ;
     RECT  38.801 60.624 38.905 60.984 ;
     RECT  38.771 62.016 38.905 63.384 ;
     RECT  38.545 67.872 38.909 67.896 ;
     RECT  38.62 72.48 38.909 73.032 ;
     RECT  37.573 77.952 38.909 77.976 ;
     RECT  38.797 74.928 38.977 74.952 ;
     RECT  38.761 81.072 38.977 81.096 ;
     RECT  37.973 82.416 38.977 83.352 ;
     RECT  38.909 72.96 39.013 73.032 ;
     RECT  38.977 74.4 39.013 74.952 ;
     RECT  38.689 51.648 39.089 52.776 ;
     RECT  39.013 72.96 39.097 74.952 ;
     RECT  38.113 79.776 39.109 79.8 ;
     RECT  38.977 81.072 39.109 83.352 ;
     RECT  39.097 73.008 39.121 74.952 ;
     RECT  39.121 73.008 39.125 75.288 ;
     RECT  39.109 79.776 39.155 83.352 ;
     RECT  39.155 80.496 39.196 83.352 ;
     RECT  39.061 78.624 39.337 78.648 ;
     RECT  38.149 56.736 39.553 59.016 ;
     RECT  38.771 64.416 39.769 64.968 ;
     RECT  38.829 55.248 39.829 55.272 ;
     RECT  39.553 56.736 39.829 59.256 ;
     RECT  38.905 60.624 39.913 63.384 ;
     RECT  39.769 64.416 39.913 65.016 ;
     RECT  38.62 69.216 39.985 70.872 ;
     RECT  39.589 50.64 40.021 50.664 ;
     RECT  40.021 50.64 40.129 51.48 ;
     RECT  39.337 78.624 40.165 79.224 ;
     RECT  35.104 25.2 40.208 25.224 ;
     RECT  38.405 49.584 40.208 49.608 ;
     RECT  40.129 50.592 40.208 51.48 ;
     RECT  39.089 52.56 40.208 52.776 ;
     RECT  39.829 55.248 40.208 59.256 ;
     RECT  39.913 60.624 40.208 65.016 ;
     RECT  38.333 66.24 40.208 66.504 ;
     RECT  39.985 68.208 40.208 70.872 ;
     RECT  39.125 73.488 40.208 75.288 ;
     RECT  38.797 76.512 40.208 76.968 ;
     RECT  40.165 77.952 40.208 79.224 ;
     RECT  39.196 80.88 40.208 83.352 ;
     RECT  40.208 2.148 40.312 84.252 ;
     RECT  40.312 2.418 40.504 83.982 ;
     RECT  40.504 54.672 40.565 59.016 ;
     RECT  40.504 52.512 40.673 53.4 ;
     RECT  40.504 50.544 40.745 51.48 ;
     RECT  40.504 60.384 41.069 64.728 ;
     RECT  40.504 76.512 41.069 76.872 ;
     RECT  40.504 77.952 41.069 80.424 ;
     RECT  41.069 78 41.116 80.424 ;
     RECT  41.069 60.384 41.213 63.576 ;
     RECT  40.504 82.176 41.321 82.296 ;
     RECT  40.565 54.672 41.393 55.848 ;
     RECT  41.069 64.656 41.429 64.728 ;
     RECT  41.069 76.512 41.429 76.584 ;
     RECT  41.393 54.672 41.537 54.696 ;
     RECT  41.393 55.824 41.557 55.848 ;
     RECT  40.565 57.408 41.557 59.016 ;
     RECT  41.557 55.824 41.603 59.016 ;
     RECT  40.504 67.728 41.605 70.872 ;
     RECT  41.116 78 41.644 79.8 ;
     RECT  40.504 25.2 41.645 25.224 ;
     RECT  41.564 80.928 41.651 80.952 ;
     RECT  40.745 50.544 41.717 51.432 ;
     RECT  40.673 53.376 41.749 53.4 ;
     RECT  40.504 66.096 41.785 66.504 ;
     RECT  40.504 74.304 41.785 74.328 ;
     RECT  41.717 50.544 41.789 50.712 ;
     RECT  41.603 55.824 41.789 57.72 ;
     RECT  41.213 60.384 41.897 61.272 ;
     RECT  41.605 67.728 41.897 71.304 ;
     RECT  41.789 55.824 41.969 57.432 ;
     RECT  41.213 62.256 41.969 63.576 ;
     RECT  41.897 60.384 42.077 60.408 ;
     RECT  41.785 74.304 42.145 74.472 ;
     RECT  41.897 68.208 42.185 71.304 ;
     RECT  41.749 53.376 42.293 53.448 ;
     RECT  41.429 64.656 42.293 64.68 ;
     RECT  42.293 53.424 42.421 53.448 ;
     RECT  42.38 35.856 42.428 35.88 ;
     RECT  42.001 52.176 42.469 52.344 ;
     RECT  41.644 78.624 42.509 79.8 ;
     RECT  41.321 82.272 42.509 82.296 ;
     RECT  42.428 35.856 42.515 36.168 ;
     RECT  41.789 50.544 42.515 50.568 ;
     RECT  41.785 66.096 42.572 66.648 ;
     RECT  42.469 52.176 42.581 52.392 ;
     RECT  42.185 68.208 42.659 70.872 ;
     RECT  41.603 58.848 42.685 59.016 ;
     RECT  42.685 3.408 42.709 3.432 ;
     RECT  42.685 58.848 42.721 59.256 ;
     RECT  42.145 73.968 42.721 74.472 ;
     RECT  41.429 76.56 42.757 76.584 ;
     RECT  42.677 35.328 42.761 35.352 ;
     RECT  42.572 66.096 42.761 67.128 ;
     RECT  41.969 55.824 42.797 56.376 ;
     RECT  41.969 62.256 42.797 63.432 ;
     RECT  42.721 73.968 42.797 74.664 ;
     RECT  42.721 58.848 42.833 59.832 ;
     RECT  42.581 52.176 42.869 52.344 ;
     RECT  42.509 79.2 42.905 79.8 ;
     RECT  42.709 3.408 42.941 3.96 ;
     RECT  42.797 74.208 42.949 74.664 ;
     RECT  42.757 76.32 42.949 76.584 ;
     RECT  42.793 50.832 42.977 50.856 ;
     RECT  42.757 72.096 43.043 72.12 ;
     RECT  42.797 55.824 43.045 55.848 ;
     RECT  41.969 57.408 43.081 57.432 ;
     RECT  42.869 52.176 43.085 52.296 ;
     RECT  43.085 52.176 43.193 52.2 ;
     RECT  42.797 62.256 43.229 63.24 ;
     RECT  42.905 79.2 43.301 79.224 ;
     RECT  42.659 68.736 43.333 70.872 ;
     RECT  42.793 81.504 43.369 81.528 ;
     RECT  43.297 0.096 43.381 0.12 ;
     RECT  43.045 55.728 43.409 55.848 ;
     RECT  42.833 58.848 43.445 59.256 ;
     RECT  43.369 81.36 43.481 81.528 ;
     RECT  42.761 66.768 43.549 67.128 ;
     RECT  43.445 58.848 43.669 58.92 ;
     RECT  42.421 53.424 43.697 54.36 ;
     RECT  43.549 82.128 43.837 82.2 ;
     RECT  42.649 83.232 43.837 83.256 ;
     RECT  43.549 66.768 43.873 67.56 ;
     RECT  43.333 68.736 43.873 71.208 ;
     RECT  43.429 1.728 43.877 1.752 ;
     RECT  43.837 82.128 43.877 83.256 ;
     RECT  43.229 62.496 44.053 63.24 ;
     RECT  43.697 54.288 44.197 54.36 ;
     RECT  43.409 55.728 44.197 55.752 ;
     RECT  44.125 83.328 44.197 83.592 ;
     RECT  44.053 62.496 44.269 63.336 ;
     RECT  43.405 72.96 44.269 73.032 ;
     RECT  42.949 74.208 44.269 76.584 ;
     RECT  44.197 83.328 44.284 84.216 ;
     RECT  42.721 78.096 44.293 78.12 ;
     RECT  44.269 72.96 44.305 76.584 ;
     RECT  43.081 57.408 44.341 57.528 ;
     RECT  42.901 86.352 44.341 86.376 ;
     RECT  44.305 72.288 44.389 76.584 ;
     RECT  44.293 78.096 44.389 78.984 ;
     RECT  43.669 58.656 44.413 58.92 ;
     RECT  44.269 62.496 44.413 63.816 ;
     RECT  44.396 64.944 44.413 64.968 ;
     RECT  44.341 56.784 44.525 57.528 ;
     RECT  43.405 51.36 44.673 52.152 ;
     RECT  43.873 66.768 44.677 71.208 ;
     RECT  44.389 72.288 44.677 78.984 ;
     RECT  44.197 54.288 44.701 55.752 ;
     RECT  44.525 56.784 44.701 57.432 ;
     RECT  44.413 62.064 44.701 63.816 ;
     RECT  44.673 51.216 44.725 52.152 ;
     RECT  43.909 53.184 44.725 53.208 ;
     RECT  44.677 66.768 44.953 78.984 ;
     RECT  44.521 80.016 44.953 80.04 ;
     RECT  44.701 61.632 44.989 63.816 ;
     RECT  44.413 64.944 44.989 65.544 ;
     RECT  43.877 82.128 45.157 82.296 ;
     RECT  44.284 83.328 45.157 83.592 ;
     RECT  44.725 51.216 45.169 53.208 ;
     RECT  44.701 54.288 45.169 57.432 ;
     RECT  44.341 85.536 45.169 86.376 ;
     RECT  44.989 61.632 45.313 65.544 ;
     RECT  45.157 81.456 45.404 83.592 ;
     RECT  45.169 51.216 45.493 57.432 ;
     RECT  44.413 58.656 45.493 59.88 ;
     RECT  45.404 81.456 45.529 83.832 ;
     RECT  45.169 84.96 45.529 86.376 ;
     RECT  45.493 51.216 45.608 59.88 ;
     RECT  45.313 61.44 45.608 65.544 ;
     RECT  44.953 66.768 45.608 80.04 ;
     RECT  45.529 81.456 45.608 86.376 ;
     RECT  45.608 2.148 45.683 86.376 ;
     RECT  45.683 2.148 45.712 84.36 ;
     RECT  45.712 2.418 45.904 84.36 ;
     RECT  45.904 81.312 46.109 84.36 ;
     RECT  45.904 58.56 46.145 80.136 ;
     RECT  45.904 52.56 46.289 57.576 ;
     RECT  46.145 58.56 46.289 60.216 ;
     RECT  46.145 61.44 46.289 80.136 ;
     RECT  46.289 64.368 46.325 80.136 ;
     RECT  45.904 51.408 46.433 51.432 ;
     RECT  46.289 54 46.505 57.576 ;
     RECT  46.325 64.368 46.541 80.04 ;
     RECT  46.541 64.368 46.595 73.32 ;
     RECT  46.541 74.352 46.757 80.04 ;
     RECT  46.595 65.856 46.829 73.32 ;
     RECT  46.757 74.4 46.829 80.04 ;
     RECT  46.829 74.4 46.901 79.848 ;
     RECT  45.683 85.488 46.931 86.376 ;
     RECT  46.595 64.368 46.937 64.728 ;
     RECT  46.289 52.56 46.969 53.016 ;
     RECT  46.289 61.44 47.009 63.336 ;
     RECT  46.931 85.536 47.117 86.376 ;
     RECT  47.117 85.536 47.161 86.28 ;
     RECT  47.161 85.536 47.219 85.56 ;
     RECT  46.829 65.856 47.261 73.272 ;
     RECT  46.505 57.216 47.293 57.576 ;
     RECT  46.289 58.56 47.293 59.832 ;
     RECT  47.293 57.216 47.333 59.832 ;
     RECT  47.009 61.632 47.369 63.24 ;
     RECT  47.333 57.216 47.405 59.256 ;
     RECT  46.969 51.936 47.437 53.016 ;
     RECT  46.505 54 47.437 55.752 ;
     RECT  47.261 65.856 47.729 72.936 ;
     RECT  46.937 64.368 47.977 64.632 ;
     RECT  46.109 81.312 48.013 83.256 ;
     RECT  46.109 84.336 48.013 84.36 ;
     RECT  46.901 74.4 48.017 79.704 ;
     RECT  48.013 81.312 48.161 84.36 ;
     RECT  48.293 85.92 48.325 85.944 ;
     RECT  47.977 64.368 48.409 65.16 ;
     RECT  47.729 66.192 48.409 72.936 ;
     RECT  47.369 62.016 48.445 63.24 ;
     RECT  48.325 85.68 48.467 85.944 ;
     RECT  48.092 60.48 48.469 60.504 ;
     RECT  48.469 60.48 48.556 60.552 ;
     RECT  48.445 61.536 48.557 63.24 ;
     RECT  47.437 51.936 48.593 55.752 ;
     RECT  48.557 62.208 48.593 63.24 ;
     RECT  48.409 66.192 48.593 73.464 ;
     RECT  47.405 57.408 48.625 59.256 ;
     RECT  48.593 62.4 48.701 63.24 ;
     RECT  48.593 52.848 48.733 55.752 ;
     RECT  48.625 57.408 48.733 60.024 ;
     RECT  48.409 64.224 48.769 65.16 ;
     RECT  48.593 66.192 48.769 70.008 ;
     RECT  48.769 64.224 48.845 70.008 ;
     RECT  48.845 64.224 48.881 69.816 ;
     RECT  48.709 86.208 48.899 86.232 ;
     RECT  47.617 50.544 48.913 50.568 ;
     RECT  48.661 51.648 48.913 51.672 ;
     RECT  48.733 52.848 48.988 60.024 ;
     RECT  48.988 58.656 48.989 60.024 ;
     RECT  48.593 71.616 49.021 73.464 ;
     RECT  48.017 74.448 49.021 79.704 ;
     RECT  48.913 50.544 49.043 51.672 ;
     RECT  48.701 62.448 49.057 63.24 ;
     RECT  48.881 64.224 49.057 64.44 ;
     RECT  48.988 52.848 49.061 57.432 ;
     RECT  49.043 51.36 49.097 51.672 ;
     RECT  48.161 81.312 49.129 83.832 ;
     RECT  49.057 62.448 49.169 64.44 ;
     RECT  49.021 71.616 49.205 79.704 ;
     RECT  48.881 66.192 49.349 69.816 ;
     RECT  49.129 81.312 49.381 83.88 ;
     RECT  49.205 74.736 49.417 79.704 ;
     RECT  49.205 71.616 49.421 73.608 ;
     RECT  49.349 66.192 49.457 68.712 ;
     RECT  49.417 74.736 49.493 79.896 ;
     RECT  49.061 52.848 49.529 54.744 ;
     RECT  49.493 74.736 49.565 77.976 ;
     RECT  49.493 79.056 49.597 79.896 ;
     RECT  49.381 81.312 49.597 84.36 ;
     RECT  49.529 54.144 49.673 54.744 ;
     RECT  49.597 79.056 49.708 84.36 ;
     RECT  49.061 55.728 49.709 57.432 ;
     RECT  49.169 63.072 49.849 64.44 ;
     RECT  49.573 85.968 49.861 86.088 ;
     RECT  49.861 85.968 49.906 86.184 ;
     RECT  49.708 79.2 49.907 84.36 ;
     RECT  49.906 85.968 49.907 86.28 ;
     RECT  49.849 63.072 49.957 64.872 ;
     RECT  49.709 57.024 50.065 57.432 ;
     RECT  48.989 58.656 50.065 59.832 ;
     RECT  49.957 63.072 50.137 64.968 ;
     RECT  49.529 52.848 50.149 53.016 ;
     RECT  49.349 69.792 50.245 69.816 ;
     RECT  50.137 62.976 50.353 65.208 ;
     RECT  50.353 62.928 50.425 65.208 ;
     RECT  49.421 71.616 50.425 71.64 ;
     RECT  50.245 69.792 50.461 70.056 ;
     RECT  50.425 71.616 50.461 71.928 ;
     RECT  49.565 74.832 50.641 77.976 ;
     RECT  49.633 61.344 50.677 61.368 ;
     RECT  50.425 62.784 50.684 65.208 ;
     RECT  49.673 54.144 50.713 54.456 ;
     RECT  49.457 66.528 50.713 68.712 ;
     RECT  50.461 69.792 50.713 71.928 ;
     RECT  49.709 55.728 50.749 55.752 ;
     RECT  50.065 57.024 50.749 59.832 ;
     RECT  50.749 55.728 50.785 59.832 ;
     RECT  50.677 60.864 50.785 61.368 ;
     RECT  50.641 74.688 50.869 77.976 ;
     RECT  49.907 79.728 50.869 84.36 ;
     RECT  45.904 34.896 51.008 34.92 ;
     RECT  49.097 51.36 51.008 51.384 ;
     RECT  50.149 52.416 51.008 53.016 ;
     RECT  50.713 54.144 51.008 54.696 ;
     RECT  50.785 55.728 51.008 61.368 ;
     RECT  50.684 62.688 51.008 65.208 ;
     RECT  50.713 66.528 51.008 71.928 ;
     RECT  49.421 72.912 51.008 73.608 ;
     RECT  50.869 74.688 51.008 84.36 ;
     RECT  49.907 86.064 51.059 86.28 ;
     RECT  51.008 2.148 51.112 84.36 ;
     RECT  51.112 2.418 51.304 84.36 ;
     RECT  51.304 55.728 51.473 56.52 ;
     RECT  51.304 60.576 51.473 60.888 ;
     RECT  51.304 66.672 51.473 72.36 ;
     RECT  51.304 73.344 51.473 80.376 ;
     RECT  51.473 74.064 51.481 80.376 ;
     RECT  51.304 50.88 51.617 53.256 ;
     RECT  51.059 86.256 51.941 86.28 ;
     RECT  51.304 81.6 51.977 84.36 ;
     RECT  51.473 66.672 52.307 67.512 ;
     RECT  51.473 56.496 52.373 56.52 ;
     RECT  51.481 74.064 52.373 79.752 ;
     RECT  51.473 60.864 52.405 60.888 ;
     RECT  51.977 81.6 52.405 84.072 ;
     RECT  51.473 68.64 52.412 72.36 ;
     RECT  51.304 62.832 52.481 65.448 ;
     RECT  52.373 74.064 52.481 78.936 ;
     RECT  52.405 81.072 52.481 84.072 ;
     RECT  52.481 74.064 52.499 74.904 ;
     RECT  51.304 58.56 52.513 59.256 ;
     RECT  52.405 60.864 52.513 61.512 ;
     RECT  52.412 68.64 52.549 72.936 ;
     RECT  51.304 54.384 52.645 54.744 ;
     RECT  52.549 55.824 52.645 55.848 ;
     RECT  51.617 52.032 52.661 53.256 ;
     RECT  52.513 58.176 52.691 59.256 ;
     RECT  52.513 60.24 52.691 61.512 ;
     RECT  51.617 50.88 52.693 50.904 ;
     RECT  52.481 75.936 52.697 78.936 ;
     RECT  52.691 58.176 52.729 59.064 ;
     RECT  52.691 60.576 52.801 61.512 ;
     RECT  52.481 62.832 52.801 63.24 ;
     RECT  52.693 50.784 52.873 50.904 ;
     RECT  52.481 81.072 52.883 83.832 ;
     RECT  52.549 68.64 52.913 73.368 ;
     RECT  52.661 52.848 52.981 53.256 ;
     RECT  52.645 54.384 52.981 55.848 ;
     RECT  52.913 68.64 53.029 70.68 ;
     RECT  52.981 52.848 53.057 55.848 ;
     RECT  52.883 81.072 53.165 83.544 ;
     RECT  52.729 57.6 53.197 59.064 ;
     RECT  52.801 60.576 53.237 63.24 ;
     RECT  53.237 62.784 53.453 63.24 ;
     RECT  52.499 74.88 53.485 74.904 ;
     RECT  52.481 64.32 53.489 65.448 ;
     RECT  53.029 67.776 53.525 70.68 ;
     RECT  52.913 72 53.593 73.368 ;
     RECT  52.307 66.672 53.629 66.696 ;
     RECT  52.873 50.784 53.633 51.048 ;
     RECT  53.485 74.88 53.633 74.952 ;
     RECT  52.697 76.416 53.665 78.936 ;
     RECT  53.165 82.272 53.705 83.544 ;
     RECT  53.057 55.104 53.741 55.848 ;
     RECT  53.489 64.32 53.741 64.488 ;
     RECT  53.165 81.072 53.741 81.096 ;
     RECT  53.665 76.416 53.849 79.176 ;
     RECT  53.705 82.272 53.885 82.968 ;
     RECT  53.525 67.824 53.921 70.68 ;
     RECT  53.809 51.456 53.989 51.48 ;
     RECT  53.633 74.928 53.989 74.952 ;
     RECT  53.741 64.32 53.993 64.392 ;
     RECT  53.197 57.12 54.065 59.064 ;
     RECT  54.065 58.416 54.133 59.064 ;
     RECT  53.237 60.576 54.133 61.512 ;
     RECT  53.849 76.464 54.173 79.176 ;
     RECT  53.885 82.656 54.173 82.968 ;
     RECT  54.092 80.256 54.179 80.28 ;
     RECT  53.989 51.456 54.205 51.672 ;
     RECT  53.057 52.848 54.277 53.784 ;
     RECT  53.741 55.104 54.277 55.608 ;
     RECT  54.133 58.416 54.281 61.512 ;
     RECT  54.281 60.384 54.313 61.512 ;
     RECT  53.453 62.784 54.313 63.144 ;
     RECT  53.629 66.096 54.389 66.696 ;
     RECT  54.205 51.456 54.421 51.768 ;
     RECT  54.277 52.848 54.421 55.608 ;
     RECT  54.173 76.464 54.461 76.632 ;
     RECT  54.313 60.384 54.533 63.144 ;
     RECT  53.993 64.32 54.533 64.344 ;
     RECT  54.241 70.944 54.601 70.968 ;
     RECT  53.593 72 54.601 73.416 ;
     RECT  54.389 66.528 54.637 66.696 ;
     RECT  54.281 58.416 54.785 58.92 ;
     RECT  54.421 51.456 54.821 55.608 ;
     RECT  54.533 60.384 54.821 60.6 ;
     RECT  54.601 70.944 54.821 73.416 ;
     RECT  54.821 51.456 54.857 55.128 ;
     RECT  54.821 73.248 54.893 73.416 ;
     RECT  53.989 74.928 54.925 75.288 ;
     RECT  54.461 76.464 54.925 76.536 ;
     RECT  54.133 81.408 54.929 81.432 ;
     RECT  54.173 77.952 54.961 79.176 ;
     RECT  54.173 82.656 55.069 82.68 ;
     RECT  54.857 51.456 55.073 54.744 ;
     RECT  54.637 66.528 55.105 66.84 ;
     RECT  53.921 67.824 55.105 69.48 ;
     RECT  55.105 66.528 55.145 69.48 ;
     RECT  54.925 74.928 55.237 76.536 ;
     RECT  54.785 58.896 55.285 58.92 ;
     RECT  55.073 51.648 55.325 54.744 ;
     RECT  54.821 70.944 55.325 71.928 ;
     RECT  54.065 57.12 55.357 57.144 ;
     RECT  55.325 51.648 55.361 54.408 ;
     RECT  55.237 74.304 55.397 76.536 ;
     RECT  55.145 66.672 55.429 69.48 ;
     RECT  54.821 60.576 55.717 60.6 ;
     RECT  54.533 61.584 55.717 63.144 ;
     RECT  55.069 82.368 55.789 82.68 ;
     RECT  55.285 58.896 55.825 59.256 ;
     RECT  55.717 60.576 55.825 63.144 ;
     RECT  55.357 56.784 55.897 57.144 ;
     RECT  55.213 64.368 55.933 64.392 ;
     RECT  55.933 64.176 56.113 64.392 ;
     RECT  54.893 73.248 56.252 73.32 ;
     RECT  55.397 74.304 56.252 75.768 ;
     RECT  55.933 55.44 56.293 55.464 ;
     RECT  55.361 51.648 56.329 54.36 ;
     RECT  56.293 55.44 56.329 55.56 ;
     RECT  55.897 56.784 56.365 57.336 ;
     RECT  55.825 58.896 56.365 63.144 ;
     RECT  56.365 56.784 56.401 63.144 ;
     RECT  56.113 64.176 56.401 65.256 ;
     RECT  55.325 71.904 56.401 71.928 ;
     RECT  51.304 34.896 56.408 34.92 ;
     RECT  56.329 51.648 56.408 55.704 ;
     RECT  56.401 56.784 56.408 65.256 ;
     RECT  55.429 66.672 56.408 69.528 ;
     RECT  56.401 71.904 56.408 72.216 ;
     RECT  56.252 73.248 56.408 75.768 ;
     RECT  54.961 77.952 56.408 79.848 ;
     RECT  55.789 82.368 56.408 82.728 ;
     RECT  56.408 2.148 56.512 84.252 ;
     RECT  56.512 2.418 56.704 83.982 ;
     RECT  56.704 78.096 56.981 82.68 ;
     RECT  56.704 51.36 56.989 60.312 ;
     RECT  56.989 51.36 57.017 59.064 ;
     RECT  56.704 69.216 57.017 72.216 ;
     RECT  57.017 71.28 57.125 72.216 ;
     RECT  57.017 58.128 57.197 59.064 ;
     RECT  56.704 62.64 57.203 64.392 ;
     RECT  57.017 51.36 57.305 57.144 ;
     RECT  56.989 60.288 57.341 60.312 ;
     RECT  56.981 81.6 57.347 82.68 ;
     RECT  57.203 63.264 57.449 64.392 ;
     RECT  57.197 58.224 57.593 59.064 ;
     RECT  57.449 63.264 57.629 64.2 ;
     RECT  56.981 78.096 57.635 80.52 ;
     RECT  57.125 71.28 57.637 71.928 ;
     RECT  56.704 75.216 57.673 77.016 ;
     RECT  56.704 67.68 57.733 67.848 ;
     RECT  57.017 69.216 57.733 70.152 ;
     RECT  57.673 75.696 57.773 77.016 ;
     RECT  56.704 73.488 57.985 74.088 ;
     RECT  57.593 58.704 58.021 59.064 ;
     RECT  57.733 67.68 58.093 70.152 ;
     RECT  57.305 51.936 58.169 57.144 ;
     RECT  57.985 62.112 58.169 62.136 ;
     RECT  57.629 64.08 58.169 64.2 ;
     RECT  58.169 64.176 58.205 64.2 ;
     RECT  58.093 67.632 58.213 70.152 ;
     RECT  58.021 61.056 58.277 61.08 ;
     RECT  57.347 82.128 58.277 82.584 ;
     RECT  57.635 78.096 58.417 79.8 ;
     RECT  58.213 67.152 58.453 70.152 ;
     RECT  57.637 71.904 58.597 71.928 ;
     RECT  57.985 73.488 58.597 74.376 ;
     RECT  58.021 58.704 58.633 59.208 ;
     RECT  58.417 78.048 58.633 79.8 ;
     RECT  58.169 51.936 58.637 55.848 ;
     RECT  57.773 75.696 58.637 76.584 ;
     RECT  58.637 51.936 58.669 54.6 ;
     RECT  58.669 51.648 58.673 54.6 ;
     RECT  58.597 71.904 58.673 74.376 ;
     RECT  58.417 61.296 58.691 61.32 ;
     RECT  58.453 66.624 58.709 70.152 ;
     RECT  58.709 66.624 58.739 69.528 ;
     RECT  58.739 67.248 58.781 69.528 ;
     RECT  58.673 71.904 58.817 72.936 ;
     RECT  58.655 83.088 58.835 83.208 ;
     RECT  58.637 75.696 58.853 76.536 ;
     RECT  58.781 69.456 58.889 69.528 ;
     RECT  58.853 75.696 58.889 75.72 ;
     RECT  58.781 67.248 58.925 68.424 ;
     RECT  58.633 78.048 58.925 80.088 ;
     RECT  58.673 51.648 59.033 54.12 ;
     RECT  58.925 78.048 59.033 78.648 ;
     RECT  58.925 79.872 59.033 80.088 ;
     RECT  58.925 67.248 59.069 68.136 ;
     RECT  58.988 64.368 59.075 64.392 ;
     RECT  58.673 74.352 59.101 74.376 ;
     RECT  59.033 79.872 59.177 79.896 ;
     RECT  58.637 55.824 59.315 55.848 ;
     RECT  58.169 56.88 59.317 57.144 ;
     RECT  59.033 51.648 59.321 53.832 ;
     RECT  59.173 62.592 59.381 62.616 ;
     RECT  59.317 56.88 59.389 57.384 ;
     RECT  58.633 58.512 59.425 59.208 ;
     RECT  58.645 60.24 59.425 60.264 ;
     RECT  59.381 62.592 59.425 62.76 ;
     RECT  59.425 62.256 59.465 62.76 ;
     RECT  58.817 72.528 59.465 72.936 ;
     RECT  58.693 81.456 59.573 81.912 ;
     RECT  59.389 56.256 59.845 57.384 ;
     RECT  59.425 58.512 59.845 60.264 ;
     RECT  59.465 62.256 59.852 62.664 ;
     RECT  58.889 69.456 59.852 69.48 ;
     RECT  59.845 56.256 59.861 60.264 ;
     RECT  59.069 67.296 59.893 68.136 ;
     RECT  59.852 69.456 59.893 69.528 ;
     RECT  59.857 71.472 59.893 71.496 ;
     RECT  59.465 72.912 59.893 72.936 ;
     RECT  59.101 74.352 59.893 74.664 ;
     RECT  59.852 61.632 59.939 62.664 ;
     RECT  59.321 52.656 60.037 53.832 ;
     RECT  59.033 78.624 60.037 78.648 ;
     RECT  59.893 72.912 60.073 74.664 ;
     RECT  60.037 52.656 60.083 53.976 ;
     RECT  60.073 72.912 60.113 75.432 ;
     RECT  59.893 70.704 60.149 71.496 ;
     RECT  60.037 78.624 60.181 78.936 ;
     RECT  60.113 72.912 60.185 74.376 ;
     RECT  60.083 53.376 60.227 53.976 ;
     RECT  59.861 56.256 60.329 59.496 ;
     RECT  60.227 53.376 60.365 53.832 ;
     RECT  60.185 74.352 60.365 74.376 ;
     RECT  59.893 67.296 60.46 69.528 ;
     RECT  59.939 62.256 60.505 62.664 ;
     RECT  60.329 59.472 60.509 59.496 ;
     RECT  60.46 67.296 60.613 67.32 ;
     RECT  60.46 68.928 60.649 69.528 ;
     RECT  60.365 53.376 60.653 53.544 ;
     RECT  60.185 72.912 60.829 72.936 ;
     RECT  60.649 68.928 60.833 70.056 ;
     RECT  60.149 71.472 61.081 71.496 ;
     RECT  60.829 72.672 61.081 72.936 ;
     RECT  60.505 62.256 61.117 63.24 ;
     RECT  60.181 78.336 61.141 78.936 ;
     RECT  61.117 61.584 61.148 63.24 ;
     RECT  60.329 56.256 61.441 57.864 ;
     RECT  61.333 58.992 61.441 59.016 ;
     RECT  61.441 56.256 61.549 59.016 ;
     RECT  61.081 71.472 61.549 72.936 ;
     RECT  61.549 71.184 61.58 72.936 ;
     RECT  61.58 71.184 61.621 73.368 ;
     RECT  61.148 61.584 61.649 63.816 ;
     RECT  60.113 75.408 61.665 75.432 ;
     RECT  61.621 71.184 61.729 73.464 ;
     RECT  61.649 61.056 61.765 63.816 ;
     RECT  58.417 65.52 61.765 65.544 ;
     RECT  56.704 34.896 61.808 34.92 ;
     RECT  59.321 51.648 61.808 51.672 ;
     RECT  60.653 53.52 61.808 53.544 ;
     RECT  61.549 56.256 61.808 59.832 ;
     RECT  61.765 61.056 61.808 65.544 ;
     RECT  60.613 67.248 61.808 67.32 ;
     RECT  60.833 68.928 61.808 69.48 ;
     RECT  61.729 71.184 61.808 73.56 ;
     RECT  61.665 75.408 61.808 75.816 ;
     RECT  60.397 77.28 61.808 77.304 ;
     RECT  61.141 78.336 61.808 79.224 ;
     RECT  61.141 80.304 61.808 80.328 ;
     RECT  59.573 81.456 61.808 81.48 ;
     RECT  61.808 2.148 61.912 84.252 ;
     RECT  61.912 2.418 62.104 83.982 ;
     RECT  62.104 57.84 62.237 57.864 ;
     RECT  62.104 67.968 62.453 72.216 ;
     RECT  62.104 56.256 62.633 56.328 ;
     RECT  62.104 62.016 62.633 63.528 ;
     RECT  62.453 67.968 62.675 71.496 ;
     RECT  62.675 70.416 62.716 71.496 ;
     RECT  62.104 64.704 62.849 64.728 ;
     RECT  62.716 70.848 62.849 71.496 ;
     RECT  62.104 77.28 62.957 77.304 ;
     RECT  62.633 56.304 62.993 56.328 ;
     RECT  62.104 74.64 62.993 75.816 ;
     RECT  62.993 74.64 63.011 75.384 ;
     RECT  62.633 62.016 63.029 63.096 ;
     RECT  62.104 73.536 63.137 73.56 ;
     RECT  62.104 66.144 63.164 66.168 ;
     RECT  63.029 62.256 63.173 63.096 ;
     RECT  63.164 66.144 63.205 66.648 ;
     RECT  62.675 67.968 63.205 68.952 ;
     RECT  63.205 66.144 63.251 68.952 ;
     RECT  63.251 67.248 63.461 68.952 ;
     RECT  63.173 63.072 63.569 63.096 ;
     RECT  62.849 70.848 63.605 70.872 ;
     RECT  63.011 74.64 63.893 74.664 ;
     RECT  63.461 67.248 64.073 67.992 ;
     RECT  64.073 67.968 64.469 67.992 ;
     RECT  62.104 34.896 67.208 34.92 ;
     RECT  62.104 51.648 67.208 51.672 ;
     RECT  62.104 53.52 67.208 53.544 ;
     RECT  67.208 2.148 67.312 84.252 ;
     RECT  67.312 2.418 67.504 83.982 ;
     RECT  67.504 34.896 72.608 34.92 ;
     RECT  67.504 51.648 72.608 51.672 ;
     RECT  67.504 53.52 72.608 53.544 ;
     RECT  72.608 2.148 72.712 84.252 ;
     RECT  72.712 2.418 72.904 83.982 ;
     RECT  72.904 34.896 78.008 34.92 ;
     RECT  72.904 51.648 78.008 51.672 ;
     RECT  72.904 53.52 78.008 53.544 ;
     RECT  78.008 2.148 78.112 84.252 ;
     RECT  78.112 2.418 78.304 83.982 ;
     RECT  78.304 51.648 80.993 51.672 ;
     RECT  78.304 34.896 82.109 34.92 ;
     RECT  78.304 53.52 82.397 53.544 ;
     RECT  83.408 2.148 83.512 84.252 ;
     RECT  83.512 2.418 83.704 83.982 ;
     RECT  83.704 32.976 84.805 33.576 ;
     RECT  84.805 32.976 84.877 33.96 ;
     RECT  83.704 52.176 84.877 53.064 ;
     RECT  84.877 52.176 84.913 53.928 ;
     RECT  84.877 32.976 85.453 34.344 ;
     RECT  84.913 52.08 85.453 53.928 ;
     RECT  85.453 32.976 85.489 34.44 ;
     RECT  85.453 51.984 85.489 54.312 ;
     RECT  85.489 32.688 86.209 34.44 ;
     RECT  86.209 32.688 86.245 34.632 ;
     RECT  85.489 51.408 86.245 54.312 ;
     RECT  86.245 32.496 86.281 34.632 ;
     RECT  86.281 32.496 86.364 34.728 ;
     RECT  86.245 51.408 86.364 54.504 ;
     RECT  86.364 32.496 86.393 32.52 ;
     RECT  86.364 34.704 86.393 34.728 ;
     RECT  86.364 54.48 86.393 54.504 ;
    LAYER M5 ;
     RECT  43.344 0.016 43.464 0.131 ;
     RECT  43.44 0.131 43.464 1.763 ;
     RECT  2.4 2.137 2.52 2.151 ;
     RECT  7.8 2.137 7.92 2.151 ;
     RECT  13.2 2.137 13.32 2.151 ;
     RECT  18.6 2.137 18.72 2.151 ;
     RECT  24 2.137 24.12 2.151 ;
     RECT  29.4 2.137 29.52 2.151 ;
     RECT  34.8 2.137 34.92 2.151 ;
     RECT  40.2 2.137 40.32 2.151 ;
     RECT  45.6 2.137 45.72 2.151 ;
     RECT  51 2.137 51.12 2.151 ;
     RECT  56.4 2.137 56.52 2.151 ;
     RECT  61.8 2.137 61.92 2.151 ;
     RECT  67.2 2.137 67.32 2.151 ;
     RECT  72.6 2.137 72.72 2.151 ;
     RECT  78 2.137 78.12 2.151 ;
     RECT  83.4 2.137 83.52 2.151 ;
     RECT  45.6 2.151 45.912 34.885 ;
     RECT  42.72 3.925 42.744 35.363 ;
     RECT  36.48 48.421 36.504 50.531 ;
     RECT  40.2 2.151 40.512 50.629 ;
     RECT  37.92 49.573 37.944 50.771 ;
     RECT  45.6 34.885 46.104 51.205 ;
     RECT  49.008 50.533 49.032 51.395 ;
     RECT  42.432 35.845 42.504 52.403 ;
     RECT  51 2.151 51.312 52.405 ;
     RECT  40.032 50.629 40.512 52.739 ;
     RECT  56.4 2.151 56.712 52.981 ;
     RECT  44.736 51.205 46.104 53.173 ;
     RECT  43.92 53.173 46.104 53.219 ;
     RECT  40.2 52.739 40.512 53.365 ;
     RECT  47.52 52.405 47.544 53.411 ;
     RECT  56.4 52.981 56.808 53.941 ;
     RECT  60.048 51.637 60.072 53.941 ;
     RECT  60.048 53.941 60.216 53.987 ;
     RECT  56.4 53.941 56.904 54.083 ;
     RECT  33.072 53.029 33.096 54.131 ;
     RECT  38.544 52.405 38.568 54.179 ;
     RECT  43.92 53.219 43.944 54.277 ;
     RECT  43.92 54.277 44.424 54.323 ;
     RECT  42.432 52.403 42.456 54.371 ;
     RECT  50.16 52.405 51.312 54.371 ;
     RECT  50.688 54.371 51.312 54.419 ;
     RECT  86.256 54.373 86.28 54.515 ;
     RECT  40.2 53.365 41.208 54.707 ;
     RECT  50.784 54.419 51.312 54.707 ;
     RECT  38.592 54.325 38.616 54.709 ;
     RECT  44.4 54.323 44.424 54.755 ;
     RECT  54.48 52.981 54.504 55.139 ;
     RECT  40.2 54.707 40.512 55.237 ;
     RECT  38.592 54.709 38.76 55.283 ;
     RECT  34.8 2.151 35.112 55.669 ;
     RECT  34.8 55.669 35.208 55.813 ;
     RECT  43.056 55.717 43.08 55.813 ;
     RECT  45.6 53.219 46.104 55.813 ;
     RECT  52.656 54.373 52.68 55.813 ;
     RECT  60.192 53.987 60.216 55.813 ;
     RECT  59.28 55.813 60.216 56.293 ;
     RECT  61.8 2.151 62.112 56.293 ;
     RECT  56.4 54.083 56.808 56.341 ;
     RECT  59.28 56.293 62.952 56.435 ;
     RECT  38.592 55.283 38.616 56.725 ;
     RECT  39.84 55.237 40.512 56.725 ;
     RECT  34.8 55.813 36.024 56.771 ;
     RECT  45.6 55.813 46.344 57.059 ;
     RECT  56.4 56.341 57.048 57.059 ;
     RECT  59.28 56.435 59.88 57.059 ;
     RECT  52.656 55.813 53.592 57.155 ;
     RECT  56.4 57.059 56.952 57.299 ;
     RECT  61.104 56.435 62.952 57.299 ;
     RECT  33.024 55.813 33.048 57.301 ;
     RECT  33.024 57.301 33.528 57.347 ;
     RECT  43.056 55.813 43.368 57.493 ;
     RECT  38.592 56.725 40.512 57.635 ;
     RECT  45.6 57.059 46.104 57.685 ;
     RECT  48.912 56.629 48.936 57.781 ;
     RECT  48.432 57.781 48.936 57.827 ;
     RECT  33.504 57.347 33.528 58.115 ;
     RECT  41.568 55.813 41.592 58.115 ;
     RECT  56.4 57.299 56.712 58.357 ;
     RECT  59.472 57.059 59.88 58.547 ;
     RECT  43.056 57.493 43.704 58.691 ;
     RECT  56.4 58.357 57 58.739 ;
     RECT  59.472 58.547 59.496 58.739 ;
     RECT  48.432 57.827 48.888 58.981 ;
     RECT  0.192 24.997 0.216 59.027 ;
     RECT  29.4 2.151 29.712 59.173 ;
     RECT  47.904 58.981 48.888 59.267 ;
     RECT  61.8 57.299 62.952 59.797 ;
     RECT  56.4 58.739 56.952 59.891 ;
     RECT  28.656 59.173 29.712 60.275 ;
     RECT  52.656 57.155 52.68 60.275 ;
     RECT  48.144 59.267 48.888 60.515 ;
     RECT  38.592 57.635 38.616 60.517 ;
     RECT  34.8 56.771 35.208 60.661 ;
     RECT  38.592 60.517 38.76 60.661 ;
     RECT  40.2 57.635 40.512 60.661 ;
     RECT  34.08 60.661 35.208 60.901 ;
     RECT  38.592 60.661 40.512 60.949 ;
     RECT  56.4 59.891 56.712 60.997 ;
     RECT  31.44 60.373 31.464 61.091 ;
     RECT  29.4 60.275 29.712 61.189 ;
     RECT  58.656 59.125 58.68 61.331 ;
     RECT  26.4 60.373 26.424 61.475 ;
     RECT  55.728 60.997 56.712 61.619 ;
     RECT  34.08 60.901 35.4 61.859 ;
     RECT  45.504 57.685 46.104 61.909 ;
     RECT  61.68 59.797 62.952 62.149 ;
     RECT  48.48 60.515 48.888 62.195 ;
     RECT  38.16 60.949 40.512 62.435 ;
     RECT  59.904 61.621 59.928 62.581 ;
     RECT  59.424 62.581 59.928 62.627 ;
     RECT  56.4 61.619 56.712 62.629 ;
     RECT  51 54.707 51.312 62.677 ;
     RECT  34.08 61.859 35.208 62.723 ;
     RECT  38.736 62.435 40.512 62.723 ;
     RECT  59.424 62.627 59.448 62.771 ;
     RECT  34.8 62.723 35.208 62.869 ;
     RECT  31.872 62.101 31.896 63.011 ;
     RECT  27.36 62.437 27.384 63.299 ;
     RECT  56.4 62.629 57.192 63.299 ;
     RECT  61.584 62.149 62.952 63.781 ;
     RECT  34.8 62.869 35.256 63.829 ;
     RECT  56.4 63.299 56.856 64.163 ;
     RECT  50.736 62.677 51.312 64.357 ;
     RECT  38.736 62.723 38.76 64.405 ;
     RECT  40.2 62.723 40.512 64.405 ;
     RECT  24 2.151 24.312 64.885 ;
     RECT  38.736 64.405 40.512 64.979 ;
     RECT  44.448 63.733 44.472 64.979 ;
     RECT  50.736 64.357 51.864 64.979 ;
     RECT  59.04 64.357 59.064 65.509 ;
     RECT  58.704 65.509 59.064 65.555 ;
     RECT  37.584 63.829 37.608 65.651 ;
     RECT  45.504 61.909 46.68 65.845 ;
     RECT  24 64.885 25.128 65.939 ;
     RECT  43.056 58.691 43.08 66.085 ;
     RECT  61.2 63.781 62.952 66.133 ;
     RECT  61.2 66.133 63.24 66.179 ;
     RECT  48.864 62.195 48.888 66.613 ;
     RECT  29.4 61.189 30.552 66.661 ;
     RECT  50.736 64.979 51.312 66.661 ;
     RECT  45.504 65.845 47.304 66.997 ;
     RECT  48.864 66.613 49.08 66.997 ;
     RECT  45.504 66.997 49.08 67.141 ;
     RECT  58.704 65.555 58.728 67.141 ;
     RECT  29.4 66.661 31.272 67.189 ;
     RECT  55.056 66.661 55.08 67.237 ;
     RECT  56.4 64.163 56.712 67.237 ;
     RECT  28.32 66.661 28.344 67.283 ;
     RECT  29.4 67.189 31.896 67.283 ;
     RECT  34.8 63.829 35.544 67.283 ;
     RECT  58.224 67.141 58.728 67.283 ;
     RECT  63.216 66.179 63.24 67.283 ;
     RECT  34.8 67.283 35.208 67.619 ;
     RECT  50.736 66.661 52.296 67.765 ;
     RECT  44.736 67.141 49.08 67.811 ;
     RECT  55.056 67.237 56.712 67.859 ;
     RECT  61.2 66.179 62.112 67.957 ;
     RECT  55.872 67.859 56.712 68.099 ;
     RECT  45.504 67.811 49.08 68.147 ;
     RECT  58.224 67.283 58.536 68.147 ;
     RECT  42.624 66.085 43.08 68.197 ;
     RECT  45.504 68.147 48.888 68.387 ;
     RECT  58.512 68.147 58.536 68.627 ;
     RECT  42.288 68.197 43.08 68.675 ;
     RECT  42.72 68.675 43.08 68.821 ;
     RECT  60.384 67.957 62.112 68.917 ;
     RECT  59.904 68.917 62.112 68.963 ;
     RECT  50.736 67.765 53.064 69.011 ;
     RECT  29.4 67.283 30.552 69.155 ;
     RECT  21.648 67.477 21.672 69.203 ;
     RECT  61.2 68.963 62.112 69.491 ;
     RECT  18.6 2.151 18.912 69.493 ;
     RECT  38.736 64.979 38.76 69.493 ;
     RECT  40.2 64.979 40.512 69.493 ;
     RECT  61.296 69.491 62.112 69.493 ;
     RECT  53.04 69.011 53.064 69.541 ;
     RECT  24 65.939 24.408 69.685 ;
     RECT  23.904 69.685 24.408 69.827 ;
     RECT  42.72 68.821 44.04 69.827 ;
     RECT  53.04 69.541 53.592 69.971 ;
     RECT  50.736 69.011 51.312 70.019 ;
     RECT  31.872 67.283 31.896 70.021 ;
     RECT  31.728 70.021 31.896 70.069 ;
     RECT  41.616 69.205 41.64 70.069 ;
     RECT  42.72 69.827 43.032 70.069 ;
     RECT  56.4 68.099 56.712 70.117 ;
     RECT  44.016 69.827 44.04 70.451 ;
     RECT  18.6 69.493 19.608 70.499 ;
     RECT  32.88 69.445 32.904 70.547 ;
     RECT  53.568 69.971 53.592 70.643 ;
     RECT  59.904 68.963 59.928 70.739 ;
     RECT  38.736 69.493 40.512 70.787 ;
     RECT  38.736 70.787 39.048 70.789 ;
     RECT  50.784 70.019 51.312 70.835 ;
     RECT  34.8 67.619 35.112 70.933 ;
     RECT  31.152 70.069 31.896 70.981 ;
     RECT  61.296 69.493 62.664 71.219 ;
     RECT  24 69.827 24.408 71.221 ;
     RECT  31.152 70.981 32.52 71.315 ;
     RECT  41.616 70.069 43.032 71.315 ;
     RECT  56.4 70.117 57.624 71.315 ;
     RECT  45.504 68.387 47.688 71.605 ;
     RECT  45.504 71.605 47.832 71.651 ;
     RECT  45.504 71.651 46.728 71.653 ;
     RECT  34.368 70.933 35.112 71.701 ;
     RECT  43.008 71.315 43.032 72.131 ;
     RECT  44.688 71.653 46.728 72.227 ;
     RECT  31.728 71.315 32.52 72.325 ;
     RECT  47.808 71.651 47.832 72.325 ;
     RECT  48.864 68.387 48.888 72.325 ;
     RECT  31.728 72.325 33.048 72.371 ;
     RECT  61.296 71.219 62.112 72.419 ;
     RECT  47.808 72.325 48.888 72.901 ;
     RECT  19.92 71.221 19.944 72.947 ;
     RECT  38.544 70.789 39.048 73.043 ;
     RECT  44.688 72.227 46.68 73.093 ;
     RECT  29.4 69.155 29.712 73.333 ;
     RECT  61.632 72.419 62.112 73.475 ;
     RECT  40.2 70.787 40.512 73.477 ;
     RECT  56.4 71.315 56.712 73.477 ;
     RECT  33.024 72.371 33.048 73.763 ;
     RECT  34.368 71.701 35.208 74.053 ;
     RECT  51 70.835 51.312 74.053 ;
     RECT  52.464 70.645 52.488 74.053 ;
     RECT  51 74.053 52.488 74.099 ;
     RECT  24 71.221 24.552 74.147 ;
     RECT  47.808 72.901 49.08 74.147 ;
     RECT  28.896 73.333 29.712 74.579 ;
     RECT  31.728 72.371 31.896 74.581 ;
     RECT  61.8 73.475 62.112 74.629 ;
     RECT  24 74.147 24.408 74.677 ;
     RECT  44.592 73.093 46.68 74.723 ;
     RECT  19.92 74.629 19.944 75.107 ;
     RECT  23.904 74.677 24.408 75.155 ;
     RECT  56.304 73.477 56.712 75.155 ;
     RECT  56.4 75.155 56.712 75.205 ;
     RECT  29.04 74.579 29.712 75.299 ;
     RECT  37.584 74.581 37.608 75.299 ;
     RECT  39.072 73.477 40.512 75.299 ;
     RECT  61.8 74.629 63 75.395 ;
     RECT  61.8 75.395 62.112 75.397 ;
     RECT  42.96 74.629 42.984 75.635 ;
     RECT  55.248 74.293 55.272 75.683 ;
     RECT  31.728 74.581 32.76 75.971 ;
     RECT  47.808 74.147 48.648 75.973 ;
     RECT  44.592 74.723 46.296 76.357 ;
     RECT  51 74.099 52.2 76.405 ;
     RECT  47.808 75.973 48.84 77.029 ;
     RECT  61.68 75.397 62.112 77.315 ;
     RECT  30.72 76.117 30.744 77.363 ;
     RECT  31.728 75.971 31.896 77.413 ;
     RECT  34.368 74.053 35.592 77.413 ;
     RECT  31.728 77.413 32.136 77.941 ;
     RECT  47.808 77.029 49.224 77.941 ;
     RECT  50.736 76.405 52.2 77.941 ;
     RECT  47.808 77.941 52.2 78.037 ;
     RECT  33.984 77.413 35.592 78.085 ;
     RECT  56.4 75.205 57.624 78.085 ;
     RECT  43.824 76.357 46.296 78.131 ;
     RECT  56.304 78.085 57.624 78.131 ;
     RECT  33.984 78.085 35.88 78.469 ;
     RECT  47.808 78.037 53.112 78.469 ;
     RECT  20.208 76.981 20.232 78.707 ;
     RECT  30.912 77.941 32.136 78.997 ;
     RECT  56.304 78.131 56.712 79.091 ;
     RECT  30.864 78.997 32.136 79.189 ;
     RECT  40.2 75.299 40.512 79.189 ;
     RECT  41.568 77.989 41.592 79.189 ;
     RECT  61.8 77.315 62.112 79.189 ;
     RECT  27.648 76.885 27.672 79.331 ;
     RECT  24 75.155 24.408 79.475 ;
     RECT  40.2 79.189 41.592 79.523 ;
     RECT  47.616 78.469 53.112 79.715 ;
     RECT  39.072 75.299 39.096 79.765 ;
     RECT  56.4 79.091 56.712 79.765 ;
     RECT  30.864 79.189 32.232 80.101 ;
     RECT  40.2 79.523 41.064 80.435 ;
     RECT  27.888 79.765 27.912 80.437 ;
     RECT  27.36 80.437 27.912 80.483 ;
     RECT  39.072 79.765 39.144 80.531 ;
     RECT  56.4 79.765 57.624 80.531 ;
     RECT  22.608 79.189 22.632 80.963 ;
     RECT  30.816 80.101 32.232 80.963 ;
     RECT  33.936 78.469 35.88 81.059 ;
     RECT  27.36 80.483 27.384 81.107 ;
     RECT  54.144 79.141 54.168 81.443 ;
     RECT  33.936 81.059 35.208 81.445 ;
     RECT  61.152 79.189 62.112 81.491 ;
     RECT  42.864 79.189 42.888 81.539 ;
     RECT  47.808 79.715 53.112 81.587 ;
     RECT  29.4 75.299 29.712 81.733 ;
     RECT  30.816 80.963 31.992 81.733 ;
     RECT  29.4 81.733 31.992 82.021 ;
     RECT  47.808 81.587 52.872 82.021 ;
     RECT  28.8 82.021 31.992 82.069 ;
     RECT  39.072 80.531 39.096 82.115 ;
     RECT  47.376 82.021 52.872 82.163 ;
     RECT  41.616 80.917 41.64 82.307 ;
     RECT  26.064 81.061 26.088 82.691 ;
     RECT  52.416 82.163 52.872 82.691 ;
     RECT  56.4 80.531 57.336 82.691 ;
     RECT  28.8 82.069 32.136 82.693 ;
     RECT  33.648 81.445 35.208 82.693 ;
     RECT  28.8 82.693 35.208 82.739 ;
     RECT  58.704 81.445 58.728 83.077 ;
     RECT  58.704 83.077 58.824 83.123 ;
     RECT  58.8 83.123 58.824 83.219 ;
     RECT  47.376 82.163 51.312 83.267 ;
     RECT  36.192 82.309 36.216 83.795 ;
     RECT  29.4 82.739 35.208 83.843 ;
     RECT  52.848 82.691 52.872 83.843 ;
     RECT  44.304 78.131 46.296 84.181 ;
     RECT  2.4 2.151 2.712 84.249 ;
     RECT  7.8 2.151 8.112 84.249 ;
     RECT  13.2 2.151 13.512 84.249 ;
     RECT  18.6 70.499 18.912 84.249 ;
     RECT  24 79.475 24.312 84.249 ;
     RECT  29.4 83.843 29.712 84.249 ;
     RECT  40.2 80.435 40.512 84.249 ;
     RECT  48.144 83.267 51.312 84.249 ;
     RECT  56.4 82.691 56.712 84.249 ;
     RECT  61.8 81.491 62.112 84.249 ;
     RECT  67.2 2.151 67.512 84.249 ;
     RECT  72.6 2.151 72.912 84.249 ;
     RECT  78 2.151 78.312 84.249 ;
     RECT  83.4 2.151 83.712 84.249 ;
     RECT  2.4 84.249 2.52 84.263 ;
     RECT  7.8 84.249 7.92 84.263 ;
     RECT  13.2 84.249 13.32 84.263 ;
     RECT  18.6 84.249 18.72 84.263 ;
     RECT  24 84.249 24.12 84.263 ;
     RECT  29.4 84.249 29.52 84.263 ;
     RECT  40.2 84.249 40.32 84.263 ;
     RECT  48.144 84.249 51.12 84.263 ;
     RECT  56.4 84.249 56.52 84.263 ;
     RECT  61.8 84.249 61.92 84.263 ;
     RECT  67.2 84.249 67.32 84.263 ;
     RECT  72.6 84.249 72.72 84.263 ;
     RECT  78 84.249 78.12 84.263 ;
     RECT  83.4 84.249 83.52 84.263 ;
     RECT  48.144 84.263 50.904 84.325 ;
     RECT  44.208 84.181 46.296 85.477 ;
     RECT  44.208 85.477 46.92 85.525 ;
     RECT  48.048 84.325 50.904 85.525 ;
     RECT  44.208 85.525 50.904 86.053 ;
     RECT  30.912 83.843 35.208 86.197 ;
     RECT  30.864 86.197 35.208 86.245 ;
     RECT  30.768 86.245 35.208 86.291 ;
     RECT  30.768 86.291 34.92 86.352 ;
     RECT  44.208 86.053 51.048 86.352 ;
     RECT  35.112 48.421 36.48 50.531 ;
     RECT  36.504 49.573 37.92 50.531 ;
     RECT  42.456 52.403 42.504 53.173 ;
     RECT  38.568 52.405 40.032 52.739 ;
     RECT  46.104 52.405 47.52 53.411 ;
     RECT  42.456 53.173 43.92 54.323 ;
     RECT  43.944 53.219 45.6 54.277 ;
     RECT  41.208 53.365 42.432 54.371 ;
     RECT  44.424 54.277 45.6 54.755 ;
     RECT  42.456 54.323 44.4 54.371 ;
     RECT  41.208 54.371 44.4 54.707 ;
     RECT  51.312 54.373 52.656 60.275 ;
     RECT  40.512 54.707 44.4 54.755 ;
     RECT  38.76 54.709 40.2 55.237 ;
     RECT  40.512 54.755 43.368 55.717 ;
     RECT  38.76 55.237 39.84 55.283 ;
     RECT  38.616 55.283 39.84 56.725 ;
     RECT  40.512 55.717 43.056 55.813 ;
     RECT  43.08 55.717 43.368 55.813 ;
     RECT  40.512 55.813 41.568 58.115 ;
     RECT  41.592 55.813 43.056 58.115 ;
     RECT  59.88 56.435 61.104 57.299 ;
     RECT  56.952 57.059 57 57.299 ;
     RECT  56.712 57.299 57 58.357 ;
     RECT  33.528 57.301 34.8 58.115 ;
     RECT  38.76 60.517 40.2 60.661 ;
     RECT  31.44 61.091 31.464 61.189 ;
     RECT  30.552 61.189 31.464 62.101 ;
     RECT  35.208 61.859 35.256 62.869 ;
     RECT  30.552 62.101 31.872 63.011 ;
     RECT  38.16 62.435 38.736 63.829 ;
     RECT  38.76 62.723 40.2 64.405 ;
     RECT  43.08 63.733 44.448 64.979 ;
     RECT  44.472 63.733 45.504 64.979 ;
     RECT  37.608 63.829 38.736 65.651 ;
     RECT  38.76 64.979 40.2 69.493 ;
     RECT  62.112 66.179 63.216 67.283 ;
     RECT  28.344 66.661 29.4 67.283 ;
     RECT  55.08 66.661 56.4 67.237 ;
     RECT  56.712 67.141 58.224 68.147 ;
     RECT  30.552 67.283 31.872 69.155 ;
     RECT  44.736 67.811 45.504 68.821 ;
     RECT  47.688 68.387 48.864 71.605 ;
     RECT  42.288 68.675 42.72 69.205 ;
     RECT  44.04 68.821 45.504 70.451 ;
     RECT  59.928 68.963 61.2 69.491 ;
     RECT  29.712 69.155 31.872 70.021 ;
     RECT  40.512 69.205 41.616 71.315 ;
     RECT  41.64 69.205 42.72 70.069 ;
     RECT  31.896 69.445 32.88 70.547 ;
     RECT  59.928 69.491 61.296 70.739 ;
     RECT  43.032 69.827 44.016 70.451 ;
     RECT  29.712 70.021 31.728 70.069 ;
     RECT  29.712 70.069 31.152 71.315 ;
     RECT  44.688 70.451 45.504 71.653 ;
     RECT  18.912 70.499 19.608 71.221 ;
     RECT  31.896 70.547 32.52 70.981 ;
     RECT  51.312 70.645 52.464 74.053 ;
     RECT  39.048 70.787 40.2 73.043 ;
     RECT  18.912 71.221 19.92 72.947 ;
     RECT  47.832 71.605 48.864 72.325 ;
     RECT  46.728 71.651 47.808 72.227 ;
     RECT  46.68 72.227 47.808 74.723 ;
     RECT  33.048 72.325 34.368 73.763 ;
     RECT  31.896 72.371 33.024 73.763 ;
     RECT  39.072 73.043 40.2 73.477 ;
     RECT  31.896 73.763 32.76 74.581 ;
     RECT  55.272 74.293 56.304 75.155 ;
     RECT  37.608 74.581 39.072 75.299 ;
     RECT  18.912 74.629 19.92 75.107 ;
     RECT  46.296 74.723 47.808 78.469 ;
     RECT  55.272 75.155 56.4 75.683 ;
     RECT  39.096 75.299 40.2 79.765 ;
     RECT  31.896 75.971 32.136 77.413 ;
     RECT  29.712 76.117 30.72 77.363 ;
     RECT  30.744 76.117 31.728 77.363 ;
     RECT  18.912 76.981 20.208 78.707 ;
     RECT  49.224 77.029 50.736 77.941 ;
     RECT  29.712 77.363 31.728 77.941 ;
     RECT  29.712 77.941 30.912 78.997 ;
     RECT  40.512 77.989 41.568 79.189 ;
     RECT  43.824 78.131 44.304 79.189 ;
     RECT  46.296 78.469 47.616 79.715 ;
     RECT  29.712 78.997 30.864 80.101 ;
     RECT  53.112 79.141 54.144 81.443 ;
     RECT  22.632 79.189 24 80.963 ;
     RECT  41.592 79.189 42.864 79.523 ;
     RECT  42.888 79.189 44.304 81.539 ;
     RECT  27.648 79.331 27.672 79.765 ;
     RECT  41.064 79.523 42.864 80.435 ;
     RECT  46.296 79.715 47.808 82.021 ;
     RECT  27.648 79.765 27.888 80.437 ;
     RECT  27.912 79.765 29.4 80.483 ;
     RECT  39.144 79.765 40.2 80.531 ;
     RECT  29.712 80.101 30.816 81.733 ;
     RECT  40.512 80.435 42.864 80.917 ;
     RECT  39.096 80.531 40.2 82.115 ;
     RECT  57.336 80.531 57.624 81.445 ;
     RECT  40.512 80.917 41.616 82.307 ;
     RECT  41.64 80.917 42.864 81.539 ;
     RECT  31.992 80.963 32.232 81.445 ;
     RECT  35.208 81.059 35.88 82.309 ;
     RECT  26.088 81.061 27.36 81.107 ;
     RECT  31.992 81.445 33.648 82.069 ;
     RECT  57.336 81.445 58.704 82.691 ;
     RECT  46.296 82.021 47.376 83.267 ;
     RECT  32.136 82.069 33.648 82.693 ;
     RECT  51.312 82.163 52.416 82.691 ;
     RECT  35.208 82.309 36.192 83.795 ;
     RECT  48.048 83.267 48.144 84.325 ;
     RECT  29.712 83.843 30.912 84.249 ;
     RECT  29.52 84.249 30.912 84.263 ;
     RECT  46.92 85.477 48.048 85.525 ;
  END
END ot_hgi_sm_pub_smrg_l2
END LIBRARY
